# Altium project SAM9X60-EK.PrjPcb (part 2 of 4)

## Sheet 05 - Processor IO Expansions.SchDoc
size B; CompanyName: Microchip Technology Inc.; Organization: Microchip Technology; Address1: 2355 West Chandler Blvd.; Address2: Chandler, AZ  85224; Address4: USA; DocumentNumber: 5; SheetNumber: 5; SheetTotal: 13; SheetTitle: Processor IO Expansions

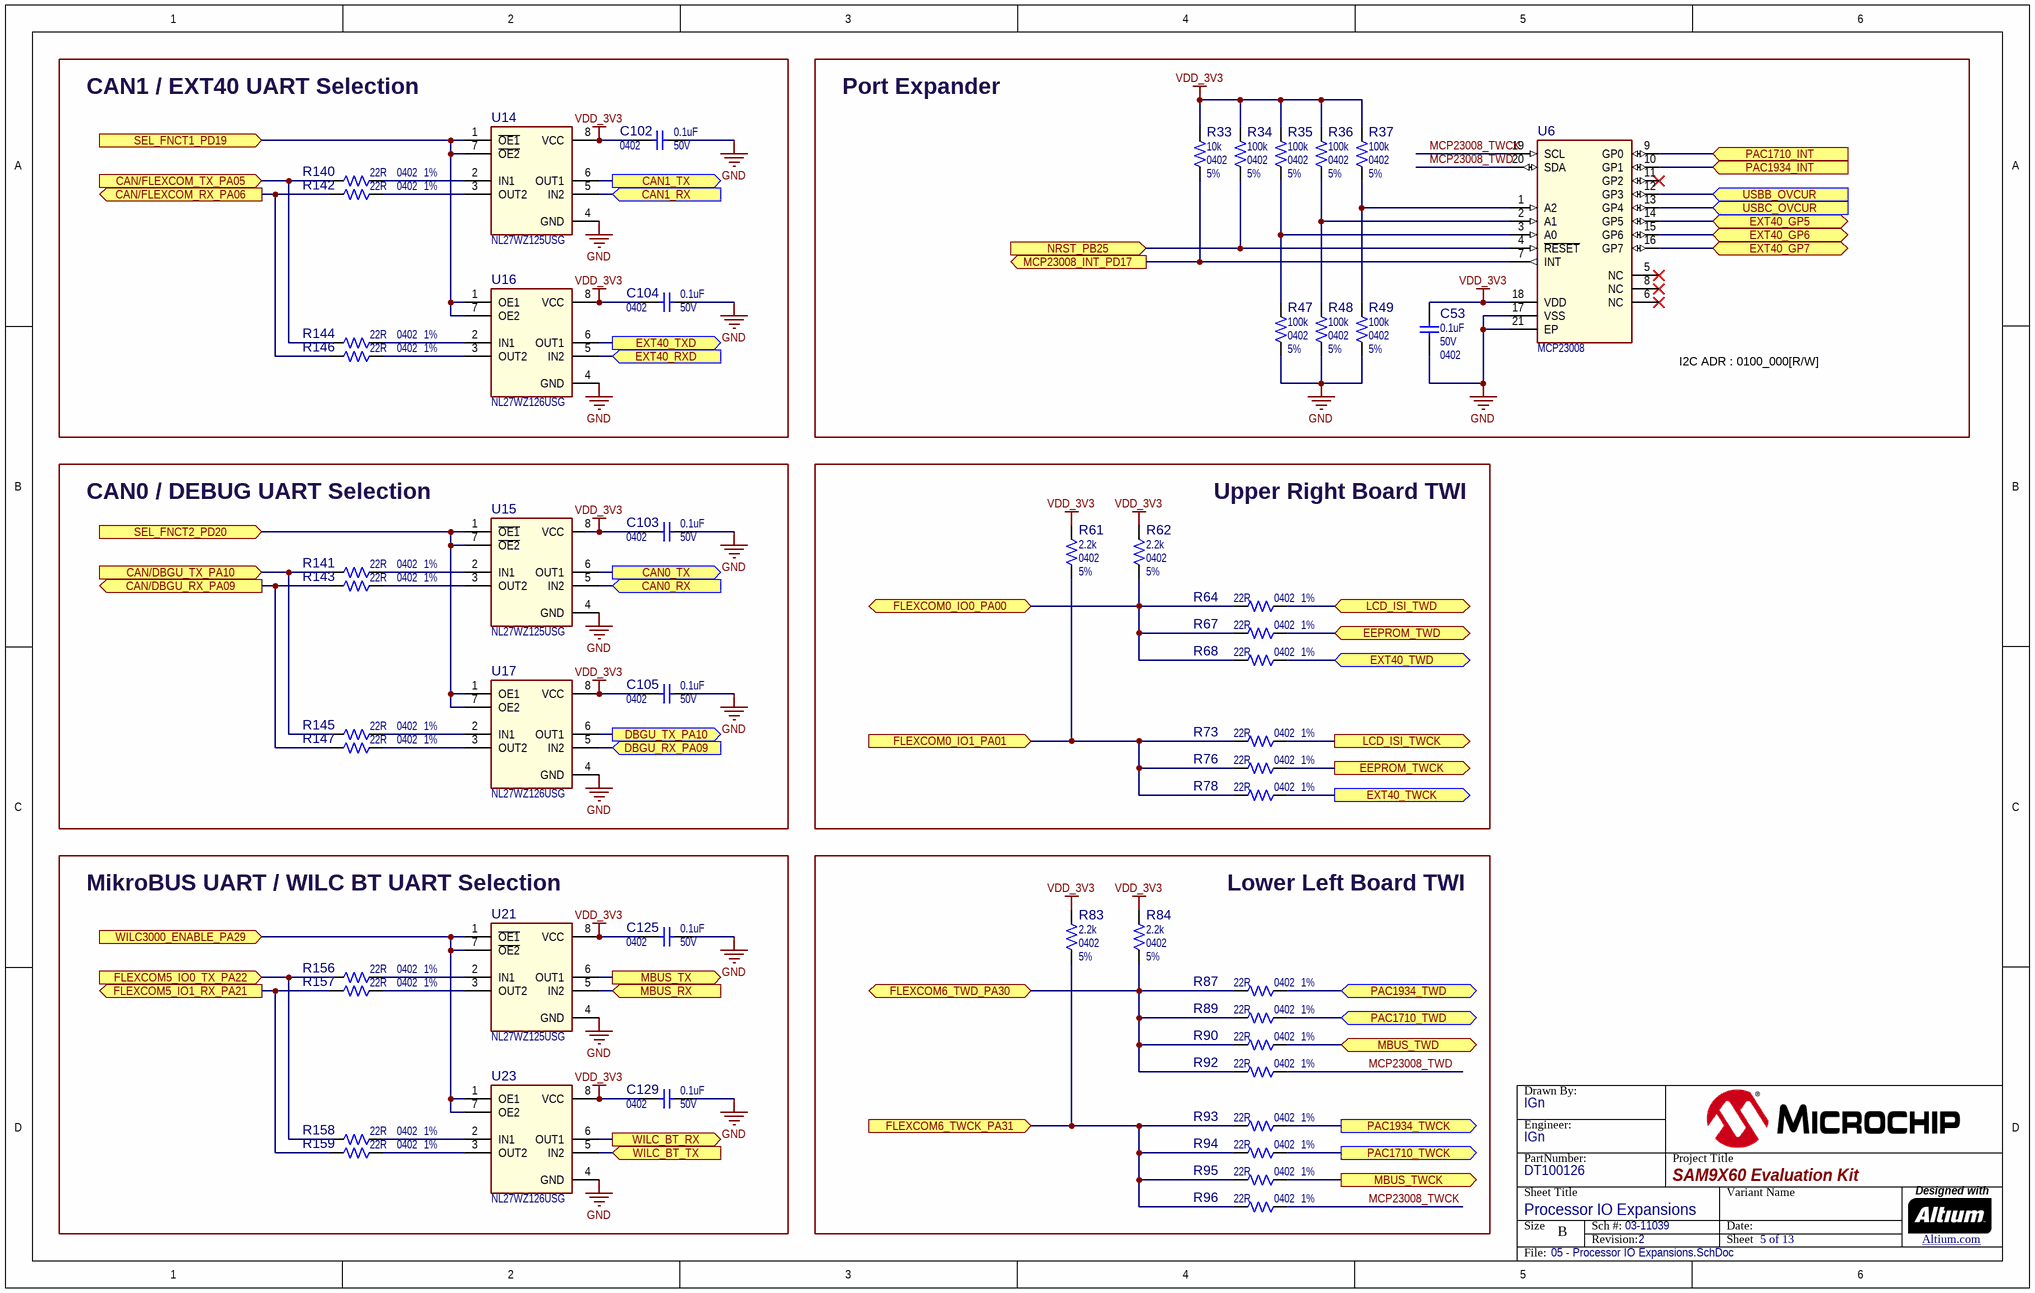
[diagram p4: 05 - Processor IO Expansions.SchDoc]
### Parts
(Parts that share a designator on the sheet are numbered #1, #2 ... from top to bottom, then left to right.)
?#5  (no value)  (graphical)
C53  value 0.1uF  Voltage: 50V  Package: 0402  [CAP_C_0402]  (hidden comment: Capacitor NP)
C102  value 0.1uF  Voltage: 50V  Package: 0402  [CAP_C_0402]  (hidden comment: Capacitor NP)
C103  value 0.1uF  Voltage: 50V  Package: 0402  [CAP_C_0402]  (hidden comment: Capacitor NP)
C104  value 0.1uF  Voltage: 50V  Package: 0402  [CAP_C_0402]  (hidden comment: Capacitor NP)
C105  value 0.1uF  Voltage: 50V  Package: 0402  [CAP_C_0402]  (hidden comment: Capacitor NP)
C125  value 0.1uF  Voltage: 50V  Package: 0402  [CAP_C_0402]  (hidden comment: Capacitor NP)
C129  value 0.1uF  Voltage: 50V  Package: 0402  [CAP_C_0402]  (hidden comment: Capacitor NP)
R33  value 10k  Package: 0402  Tolerance: 5%  [RES_C_0402]  (hidden comment: Resistor)
R34  value 100k  Package: 0402  Tolerance: 5%  [RES_C_0402]  (hidden comment: Resistor)
R35  value 100k  Package: 0402  Tolerance: 5%  [RES_C_0402]  (hidden comment: Resistor)
R36  value 100k  Package: 0402  Tolerance: 5%  [RES_C_0402]  (hidden comment: Resistor)
R37  value 100k  Package: 0402  Tolerance: 5%  [RES_C_0402]  (hidden comment: Resistor)
R47  value 100k  Package: 0402  Tolerance: 5%  [RES_C_0402]  (hidden comment: Resistor)
R48  value 100k  Package: 0402  Tolerance: 5%  [RES_C_0402]  (hidden comment: Resistor)
R49  value 100k  Package: 0402  Tolerance: 5%  [RES_C_0402]  (hidden comment: Resistor)
R61  value 2.2k  Package: 0402  Tolerance: 5%  [RES_C_0402]  (hidden comment: Resistor)
R62  value 2.2k  Package: 0402  Tolerance: 5%  [RES_C_0402]  (hidden comment: Resistor)
R64  value 22R  Package: 0402  Tolerance: 1%  [RES_C_0402]  (hidden comment: Resistor)
R67  value 22R  Package: 0402  Tolerance: 1%  [RES_C_0402]  (hidden comment: Resistor)
R68  value 22R  Package: 0402  Tolerance: 1%  [RES_C_0402]  (hidden comment: Resistor)
R73  value 22R  Package: 0402  Tolerance: 1%  [RES_C_0402]  (hidden comment: Resistor)
R76  value 22R  Package: 0402  Tolerance: 1%  [RES_C_0402]  (hidden comment: Resistor)
R78  value 22R  Package: 0402  Tolerance: 1%  [RES_C_0402]  (hidden comment: Resistor)
R83  value 2.2k  Package: 0402  Tolerance: 5%  [RES_C_0402]  (hidden comment: Resistor)
R84  value 2.2k  Package: 0402  Tolerance: 5%  [RES_C_0402]  (hidden comment: Resistor)
R87  value 22R  Package: 0402  Tolerance: 1%  [RES_C_0402]  (hidden comment: Resistor)
R89  value 22R  Package: 0402  Tolerance: 1%  [RES_C_0402]  (hidden comment: Resistor)
R90  value 22R  Package: 0402  Tolerance: 1%  [RES_C_0402]  (hidden comment: Resistor)
R92  value 22R  Package: 0402  Tolerance: 1%  [RES_C_0402]  (hidden comment: Resistor)
R93  value 22R  Package: 0402  Tolerance: 1%  [RES_C_0402]  (hidden comment: Resistor)
R94  value 22R  Package: 0402  Tolerance: 1%  [RES_C_0402]  (hidden comment: Resistor)
R95  value 22R  Package: 0402  Tolerance: 1%  [RES_C_0402]  (hidden comment: Resistor)
R96  value 22R  Package: 0402  Tolerance: 1%  [RES_C_0402]  (hidden comment: Resistor)
R140  value 22R  Package: 0402  Tolerance: 1%  [RES_C_0402]  (hidden comment: Resistor)
R141  value 22R  Package: 0402  Tolerance: 1%  [RES_C_0402]  (hidden comment: Resistor)
R142  value 22R  Package: 0402  Tolerance: 1%  [RES_C_0402]  (hidden comment: Resistor)
R143  value 22R  Package: 0402  Tolerance: 1%  [RES_C_0402]  (hidden comment: Resistor)
R144  value 22R  Package: 0402  Tolerance: 1%  [RES_C_0402]  (hidden comment: Resistor)
R145  value 22R  Package: 0402  Tolerance: 1%  [RES_C_0402]  (hidden comment: Resistor)
R146  value 22R  Package: 0402  Tolerance: 1%  [RES_C_0402]  (hidden comment: Resistor)
R147  value 22R  Package: 0402  Tolerance: 1%  [RES_C_0402]  (hidden comment: Resistor)
R156  value 22R  Package: 0402  Tolerance: 1%  [RES_C_0402]  (hidden comment: Resistor)
R157  value 22R  Package: 0402  Tolerance: 1%  [RES_C_0402]  (hidden comment: Resistor)
R158  value 22R  Package: 0402  Tolerance: 1%  [RES_C_0402]  (hidden comment: Resistor)
R159  value 22R  Package: 0402  Tolerance: 1%  [RES_C_0402]  (hidden comment: Resistor)
U6  value MCP23008  [QFN-20_4x4]  (hidden comment: MCP23008 QFN-20)
U14  value NL27WZ125USG  [US-8]  (hidden comment: NL27WZ125 US-8)
U15  value NL27WZ125USG  [US-8]  (hidden comment: NL27WZ125 US-8)
U16  value NL27WZ126USG  [US-8]  (hidden comment: NL27WZ126 US-8)
U17  value NL27WZ126USG  [US-8]  (hidden comment: NL27WZ126 US-8)
U21  value NL27WZ125USG  [US-8]  (hidden comment: NL27WZ125 US-8)
U23  value NL27WZ126USG  [US-8]  (hidden comment: NL27WZ126 US-8)

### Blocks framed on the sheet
CAN1 / EXT40 UART Selection: C102 C104 R140 R142 R144 R146 U14 U16
Port Expander: C53 R33-R37 R47-R49 U6
CAN0 / DEBUG UART Selection: C103 C105 R141 R143 R145 R147 U15 U17
Upper Right Board TWI: R61 R62 R64 R67 R68 R73 R76 R78
MikroBUS UART / WILC BT UART Selection: C125 C129 R156-R159 U21 U23
Lower Left Board TWI: R83 R84 R87 R89 R90 R92-R96

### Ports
CAN0_RX (in), CAN0_TX (out), CAN1_RX (in), CAN1_TX (out), CAN/DBGU_RX_PA09 (out), CAN/DBGU_TX_PA10 (in), CAN/FLEXCOM_RX_PA06 (out), CAN/FLEXCOM_TX_PA05 (in), DBGU_RX_PA09 (in), DBGU_TX_PA10 (out), EEPROM_TWCK (out), EEPROM_TWD (bidir), EXT40_GP5 (bidir), EXT40_GP6 (bidir), EXT40_GP7 (bidir), EXT40_RXD (in), EXT40_TWCK (out), EXT40_TWD (bidir), EXT40_TXD (out), FLEXCOM0_IO0_PA00 (bidir), FLEXCOM0_IO1_PA01 (in), FLEXCOM5_IO0_TX_PA22 (in), FLEXCOM5_IO1_RX_PA21 (out), FLEXCOM6_TWCK_PA31 (in), FLEXCOM6_TWD_PA30 (bidir), LCD_ISI_TWCK (out), LCD_ISI_TWD (bidir), MBUS_RX (in), MBUS_TWCK (out), MBUS_TWD (bidir), MBUS_TX (out), MCP23008_INT_PD17 (out), NRST_PB25 (in), PAC1710_INT (in), PAC1710_TWCK (out), PAC1710_TWD (bidir), PAC1934_INT (in), PAC1934_TWCK (out), PAC1934_TWD (bidir), SEL_FNCT1_PD19 (in), SEL_FNCT2_PD20 (in), USBB_OVCUR (in), USBC_OVCUR (in), WILC3000_ENABLE_PA29 (in), WILC_BT_RX (out), WILC_BT_TX (in)

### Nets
GND: C53.2 C102.2 C103.2 C104.2 C105.2 C125.2 C129.2 R47.1 R48.1 R49.1 U6.17(VSS) U6.21(EP) U14.4(GND) U15.4(GND) U16.4(GND) U17.4(GND) U21.4(GND) U23.4(GND)
VDD_3V3: C53.1 C102.1 C103.1 C104.1 C105.1 C125.1 C129.1 R33.2 R34.2 R35.2 R36.2 R37.2 R61.2 R62.2 R83.2 R84.2 U6.18(VDD) U14.8(VCC) U15.8(VCC) U16.8(VCC) U17.8(VCC) U21.8(VCC) U23.8(VCC)
CAN0_RX: U15.5(IN2) ; port CAN0_RX
CAN0_TX: U15.6(OUT1) ; port CAN0_TX
CAN1_RX: U14.5(IN2) ; port CAN1_RX
CAN1_TX: U14.6(OUT1) ; port CAN1_TX
CAN/DBGU_RX_PA09: R143.2 R147.2 ; port CAN/DBGU_RX_PA09
CAN/DBGU_TX_PA10: R141.2 R145.2 ; port CAN/DBGU_TX_PA10
CAN/FLEXCOM_RX_PA06: R142.2 R146.2 ; port CAN/FLEXCOM_RX_PA06
CAN/FLEXCOM_TX_PA05: R140.2 R144.2 ; port CAN/FLEXCOM_TX_PA05
DBGU_RX_PA09: U17.5(IN2) ; port DBGU_RX_PA09
DBGU_TX_PA10: U17.6(OUT1) ; port DBGU_TX_PA10
EEPROM_TWCK: R76.2 ; port EEPROM_TWCK
EEPROM_TWD: R67.2 ; port EEPROM_TWD
EXT40_GP5: U6.14(GP5) ; port EXT40_GP5
EXT40_GP6: U6.15(GP6) ; port EXT40_GP6
EXT40_GP7: U6.16(GP7) ; port EXT40_GP7
EXT40_RXD: U16.5(IN2) ; port EXT40_RXD
EXT40_TWCK: R78.2 ; port EXT40_TWCK
EXT40_TWD: R68.2 ; port EXT40_TWD
EXT40_TXD: U16.6(OUT1) ; port EXT40_TXD
FLEXCOM0_IO0_PA00: R62.1 R64.1 R67.1 R68.1 ; port FLEXCOM0_IO0_PA00
FLEXCOM0_IO1_PA01: R61.1 R73.1 R76.1 R78.1 ; port FLEXCOM0_IO1_PA01
FLEXCOM5_IO0_TX_PA22: R156.2 R158.2 ; port FLEXCOM5_IO0_TX_PA22
FLEXCOM5_IO1_RX_PA21: R157.2 R159.2 ; port FLEXCOM5_IO1_RX_PA21
FLEXCOM6_TWCK_PA31: R83.1 R93.1 R94.1 R95.1 R96.1 ; port FLEXCOM6_TWCK_PA31
FLEXCOM6_TWD_PA30: R84.1 R87.1 R89.1 R90.1 R92.1 ; port FLEXCOM6_TWD_PA30
LCD_ISI_TWCK: R73.2 ; port LCD_ISI_TWCK
LCD_ISI_TWD: R64.2 ; port LCD_ISI_TWD
MBUS_RX: U21.5(IN2) ; port MBUS_RX
MBUS_TWCK: R95.2 ; port MBUS_TWCK
MBUS_TWD: R90.2 ; port MBUS_TWD
MBUS_TX: U21.6(OUT1) ; port MBUS_TX
MCP23008_INT_PD17: R33.1 U6.7(INT) ; port MCP23008_INT_PD17
MCP23008_TWCK: R96.2 U6.19(SCL)
MCP23008_TWD: R92.2 U6.20(SDA)
NRST_PB25: R34.1 U6.4(~{RESET}) ; port NRST_PB25
PAC1710_INT: U6.9(GP0) ; port PAC1710_INT
PAC1710_TWCK: R94.2 ; port PAC1710_TWCK
PAC1710_TWD: R89.2 ; port PAC1710_TWD
PAC1934_INT: U6.10(GP1) ; port PAC1934_INT
PAC1934_TWCK: R93.2 ; port PAC1934_TWCK
PAC1934_TWD: R87.2 ; port PAC1934_TWD
SEL_FNCT1_PD19: U14.1(~{OE1}) U14.7(~{OE2}) U16.1(OE1) U16.7(OE2) ; port SEL_FNCT1_PD19
SEL_FNCT2_PD20: U15.1(~{OE1}) U15.7(~{OE2}) U17.1(OE1) U17.7(OE2) ; port SEL_FNCT2_PD20
USBB_OVCUR: U6.12(GP3) ; port USBB_OVCUR
USBC_OVCUR: U6.13(GP4) ; port USBC_OVCUR
WILC3000_ENABLE_PA29: U21.1(~{OE1}) U21.7(~{OE2}) U23.1(OE1) U23.7(OE2) ; port WILC3000_ENABLE_PA29
WILC_BT_RX: U23.6(OUT1) ; port WILC_BT_RX
WILC_BT_TX: U23.5(IN2) ; port WILC_BT_TX
NetR35_1: R35.1 R47.2 U6.3(A0)
NetR36_1: R36.1 R48.2 U6.2(A1)
NetR37_1: R37.1 R49.2 U6.1(A2)
NetR140_1: R140.1 U14.2(IN1)
NetR141_1: R141.1 U15.2(IN1)
NetR142_1: R142.1 U14.3(OUT2)
NetR143_1: R143.1 U15.3(OUT2)
NetR144_1: R144.1 U16.2(IN1)
NetR145_1: R145.1 U17.2(IN1)
NetR146_1: R146.1 U16.3(OUT2)
NetR147_1: R147.1 U17.3(OUT2)
NetR156_1: R156.1 U21.2(IN1)
NetR157_1: R157.1 U21.3(OUT2)
NetR158_1: R158.1 U23.2(IN1)
NetR159_1: R159.1 U23.3(OUT2)

Not connected (* = marked no-connect by the designer): U6 5(NC)* 6(NC)* 8(NC)* 11(GP2)*

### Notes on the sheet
- (near U6) I2C ADR : 0100_000[R/W]

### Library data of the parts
?#5 = Title Block B
C53 C102-C105 C125 C129 = CAP1463: Capacitor; Manufacturer 1: TDK Corporation; Manufacturer Part Number 1: C1005X7R1H104K050BB; Description_: CAP CER 0.1uF 50V 10% X7R SMD 0402; Dev Tools Status: Production; Tolerance: 10%; Temperature Coeffcient: X7R; Type: Ceramic; Owner: Jamus Griego; Populated: YES
R33 = RSMT0439: Manufacturer 1: Vishay; Manufacturer Part Number 1: CRCW040210K0JNED; Description_: RES TKF 10k 5% 1/16W SMD 0402; Dev Tools Status: Production; Voltage: 50V; Temperature Coeffcient: 100ppm/C; Power: 1/16W; Populated: Yes
R34 R47-R49 = RES2196: Manufacturer 1: Yageo; Manufacturer Part Number 1: RC0402JR-07100KL; Description_: RES TKF 100k 5% 1/16W SMD 0402; Dev Tools Status: Design; Temperature Coeffcient: 100ppm/C; Power: 1/16W; Owner: Ilie Galan; Populated: YES
R35-R37 = RES2196: Manufacturer 1: Yageo; Manufacturer Part Number 1: RC0402JR-07100KL; Description_: RES TKF 100k 5% 1/16W SMD 0402; Dev Tools Status: Design; Temperature Coeffcient: 100ppm/C; Power: 1/16W; Owner: Ilie Galan; Populated: DNP
R61 R62 R83 R84 = RES1020: Manufacturer 1: Vishay Dale; Manufacturer Part Number 1: CRCW04022K20JNED; Description_: RES TKF 2.2k 5% 1/16W SMD 0402; Dev Tools Status: Production; Voltage: 50V; Temperature Coeffcient: 200ppm/C; Power: 1/16W; Owner: Tad Ahlvers; Populated: YES
R64 R67 R68 R73 R76 R78 R87 R89 R90 R92-R96 R140-R147 R156-R159 = RES1474: Manufacturer 1: Panasonic Electronic Components; Manufacturer Part Number 1: ERJ-2RKF22R0X; Description_: RES TKF 22R 1% 1/20W SMD 0402; Dev Tools Status: Production; Temperature Coeffcient: 100ppm/C; Circuit Type: Isolated; Power: 1/10W; Owner: Mike Ragsdale; Populated: YES
U6 = MIC2806: I/O Expander; Manufacturer 1: Microchip; Manufacturer Part Number 1: MCP23008T-E/ML; Description_: MCHP INTERFACE GPIO-PORT EXPAND I2C 8-Port MCP23008-E/ML QFN-20; MAPS Description: 8 BIT INPUT/OUTPUT EXPANDER, I2C INTERFACE; Dev Tools Status: Production; MPC: C5BQ1YG4XA00; LeadContent: Pb-FREE; PackingMedia: T/R; Stage: REL; LeadCount: 20; PackageWidth: 4x4x0.9mm; ForceMinOrderQtyMult: True; MinOrderQty: 1; TempRange: -40C to +125C; tblDeviceFamilyID: 1180; OperatingVoltageMin: 1.8; OperatingVoltageMax: 5.5; IOpins: 8; Interface: 524288; Speed: 1.7M; HWAddressPins: 3; ResetPin: Yes; PinCurrent: 25; TotalCurrent: 160; IOVoltageTolerant: VDD
U14 U15 U21 = IC1512: BUFFER DL TRI-ST NON-INV; Manufacturer 1: ON Semiconductor; MCHP-ID: IC1512; Description_: IC BUFFER NL27WZ125USG DUAL TRI-ST NON-INV US-8; Dev Tools Status: Design; Vin: 5V; Owner: Ciprian Abramov; Populated: YES
U16 U17 U23 = IC1514: BUFFER DL TRI-ST NON-INV; Manufacturer 1: ON Semiconductor; MCHP-ID: IC1514; Description_: IC BUFFER NL27WZ126USG DUAL TRI-ST NON-INV US-8; Dev Tools Status: Design; Vin: 5V; Owner: Ciprian Abramov; Populated: YES

## Sheet 06 - On Board Memories.SchDoc
size B; CompanyName: Microchip Technology Inc.; Organization: Microchip Technology; Address1: 2355 West Chandler Blvd.; Address2: Chandler, AZ  85224; Address4: USA; DocumentNumber: 6; SheetNumber: 6; SheetTotal: 13; SheetTitle: On Board Memories

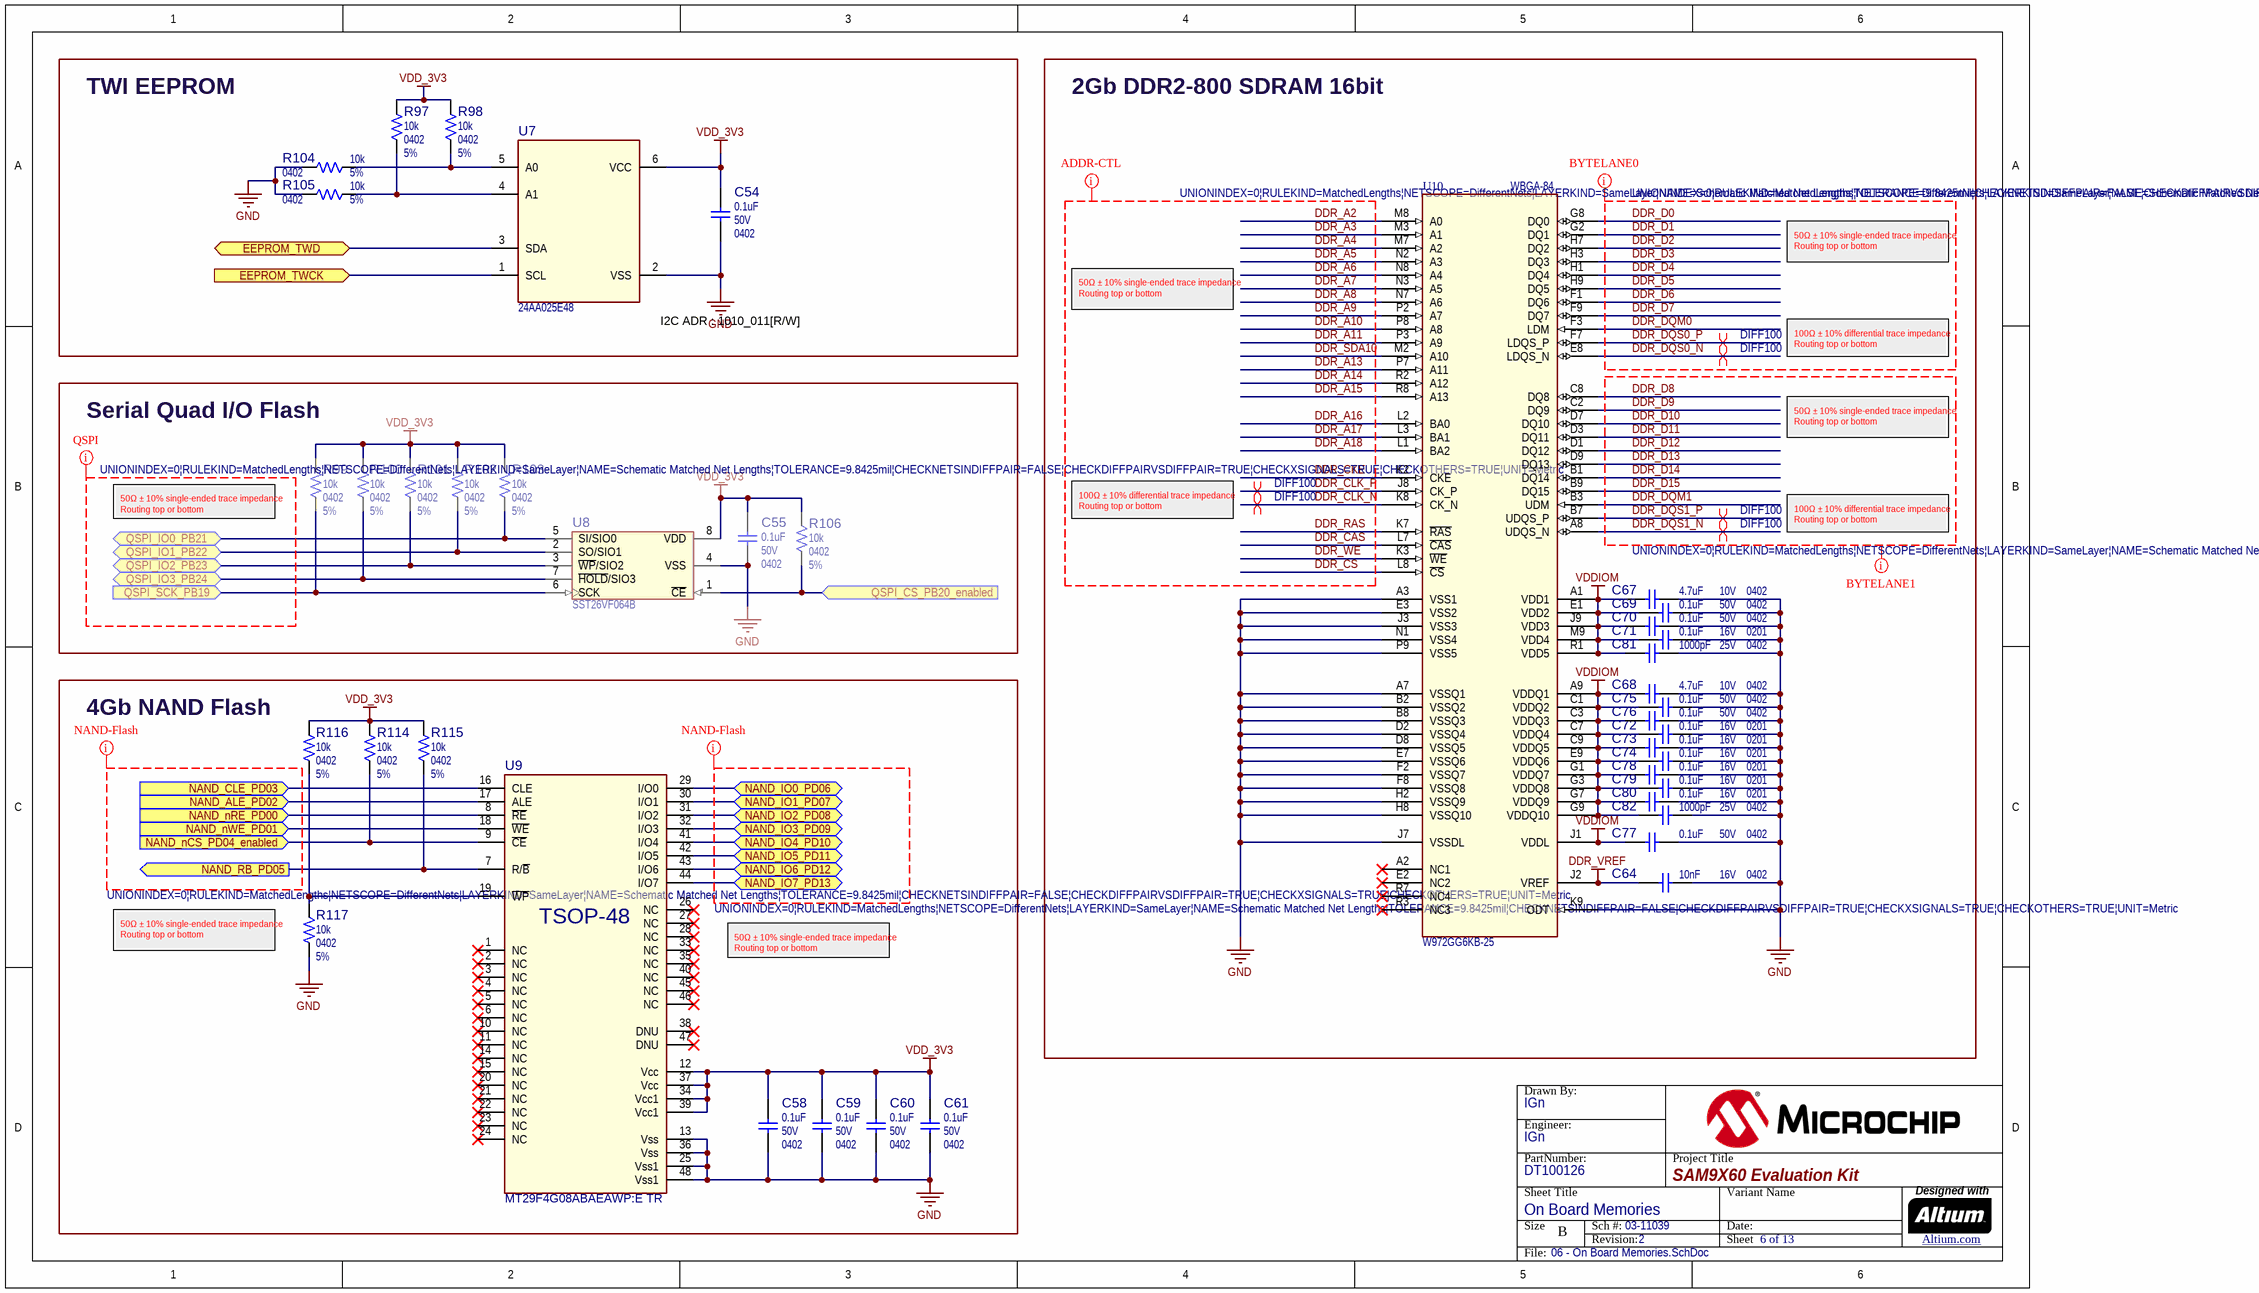
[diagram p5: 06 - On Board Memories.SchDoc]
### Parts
(Parts that share a designator on the sheet are numbered #1, #2 ... from top to bottom, then left to right.)
?#6  (no value)  (graphical)
C54  value 0.1uF  Voltage: 50V  Package: 0402  [CAP_C_0402]  (hidden comment: Capacitor NP)
C55  value 0.1uF  Voltage: 50V  Package: 0402  [CAP_C_0402]  (hidden comment: Capacitor NP)
C58  value 0.1uF  Voltage: 50V  Package: 0402  [CAP_C_0402]  (hidden comment: Capacitor NP)
C59  value 0.1uF  Voltage: 50V  Package: 0402  [CAP_C_0402]  (hidden comment: Capacitor NP)
C60  value 0.1uF  Voltage: 50V  Package: 0402  [CAP_C_0402]  (hidden comment: Capacitor NP)
C61  value 0.1uF  Voltage: 50V  Package: 0402  [CAP_C_0402]  (hidden comment: Capacitor NP)
C64  value 10nF  Voltage: 16V  Package: 0402  [CAP_C_0402]  (hidden comment: Capacitor NP)
C67  value 4.7uF  Voltage: 10V  Package: 0402  [CAP_C_0402]  (hidden comment: Capacitor NP)
C68  value 4.7uF  Voltage: 10V  Package: 0402  [CAP_C_0402]  (hidden comment: Capacitor NP)
C69  value 0.1uF  Voltage: 50V  Package: 0402  [CAP_C_0402]  (hidden comment: Capacitor NP)
C70  value 0.1uF  Voltage: 50V  Package: 0402  [CAP_C_0402]  (hidden comment: Capacitor NP)
C71  value 0.1uF  Voltage: 16V  Package: 0201  [CAP_C_0201]  (hidden comment: Capacitor NP)
C72  value 0.1uF  Voltage: 16V  Package: 0201  [CAP_C_0201]  (hidden comment: Capacitor NP)
C73  value 0.1uF  Voltage: 16V  Package: 0201  [CAP_C_0201]  (hidden comment: Capacitor NP)
C74  value 0.1uF  Voltage: 16V  Package: 0201  [CAP_C_0201]  (hidden comment: Capacitor NP)
C75  value 0.1uF  Voltage: 50V  Package: 0402  [CAP_C_0402]  (hidden comment: Capacitor NP)
C76  value 0.1uF  Voltage: 50V  Package: 0402  [CAP_C_0402]  (hidden comment: Capacitor NP)
C77  value 0.1uF  Voltage: 50V  Package: 0402  [CAP_C_0402]  (hidden comment: Capacitor NP)
C78  value 0.1uF  Voltage: 16V  Package: 0201  [CAP_C_0201]  (hidden comment: Capacitor NP)
C79  value 0.1uF  Voltage: 16V  Package: 0201  [CAP_C_0201]  (hidden comment: Capacitor NP)
C80  value 0.1uF  Voltage: 16V  Package: 0201  [CAP_C_0201]  (hidden comment: Capacitor NP)
C81  value 1000pF  Voltage: 25V  Package: 0402  [CAP_C_0402]  (hidden comment: Capacitor NP)
C82  value 1000pF  Voltage: 25V  Package: 0402  [CAP_C_0402]  (hidden comment: Capacitor NP)
R97  value 10k  Package: 0402  Tolerance: 5%  [RES_C_0402]  (hidden comment: Resistor)
R98  value 10k  Package: 0402  Tolerance: 5%  [RES_C_0402]  (hidden comment: Resistor)
R99  value 10k  Package: 0402  Tolerance: 5%  [RES_C_0402]  (hidden comment: Resistor)
R100  value 10k  Package: 0402  Tolerance: 5%  [RES_C_0402]  (hidden comment: Resistor)
R101  value 10k  Package: 0402  Tolerance: 5%  [RES_C_0402]  (hidden comment: Resistor)
R102  value 10k  Package: 0402  Tolerance: 5%  [RES_C_0402]  (hidden comment: Resistor)
R103  value 10k  Package: 0402  Tolerance: 5%  [RES_C_0402]  (hidden comment: Resistor)
R104  value 10k  Package: 0402  Tolerance: 5%  [RES_C_0402]  (hidden comment: Resistor)
R105  value 10k  Package: 0402  Tolerance: 5%  [RES_C_0402]  (hidden comment: Resistor)
R106  value 10k  Package: 0402  Tolerance: 5%  [RES_C_0402]  (hidden comment: Resistor)
R114  value 10k  Package: 0402  Tolerance: 5%  [RES_C_0402]  (hidden comment: Resistor)
R115  value 10k  Package: 0402  Tolerance: 5%  [RES_C_0402]  (hidden comment: Resistor)
R116  value 10k  Package: 0402  Tolerance: 5%  [RES_C_0402]  (hidden comment: Resistor)
R117  value 10k  Package: 0402  Tolerance: 5%  [RES_C_0402]  (hidden comment: Resistor)
U7  value 24AA025E48  [SOT-23-6]  (hidden comment: 24XXXX SOT-23-6)
U8  value SST26VF064B  [SOIJ-8]  (hidden comment: SST26VFXXX SOIC-8_WSON-8_SOIJ-8)
U9  value MT29F4G08ABAEAWP:E TR  Package: TSOP-48  [TSOP-48_P0.5]  (hidden comment: MT29F4G08ABA TSOP-48)
U10  value W972GG6KB-25  Package: WBGA-84  [WBGA-84_P0.8_8x12.5x1.2]  (hidden comment: W972GG6KB-25 WBGA-84)

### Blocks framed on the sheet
TWI EEPROM: C54 R97 R98 R104 R105 U7
2Gb DDR2-800 SDRAM 16bit: C64 C67-C82 U10
Serial Quad I/O Flash: C55 R99-R103 R106 U8
4Gb NAND Flash: C58-C61 R114-R117 U9

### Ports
EEPROM_TWCK (in), EEPROM_TWD (bidir), NAND_ALE_PD02 (in), NAND_CLE_PD03 (in), NAND_IO0_PD06 (bidir), NAND_IO1_PD07 (bidir), NAND_IO2_PD08 (bidir), NAND_IO3_PD09 (bidir), NAND_IO4_PD10 (bidir), NAND_IO5_PD11 (bidir), NAND_IO6_PD12 (bidir), NAND_IO7_PD13 (bidir), NAND_nCS_PD04_enabled (in), NAND_nRE_PD00 (in), NAND_nWE_PD01 (in), NAND_RB_PD05 (out), QSPI_CS_PB20_enabled (in), QSPI_IO0_PB21 (bidir), QSPI_IO1_PB22 (bidir), QSPI_IO2_PB23 (bidir), QSPI_IO3_PB24 (bidir), QSPI_SCK_PB19 (in)

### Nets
DDR_VREF: C64.1 U10.J2(VREF)
GND: C54.2 C55.2 C58.2 C59.2 C60.2 C61.2 C64.2 C67.1 C68.1 C69.2 C70.2 C71.1 C72.1 C73.1 C74.1 C75.2 C76.2 C77.2 C78.1 C79.1 C80.1 C81.1 C82.1 R104.2 R105.2 R117.1 U7.2(VSS) U8.4(VSS) U9.13(Vss) U9.25(Vss1) U9.36(Vss) U9.48(Vss1) U10.A3(VSS1) U10.A7(VSSQ1) U10.B2(VSSQ2) U10.B8(VSSQ3) U10.D2(VSSQ4) U10.D8(VSSQ5) U10.E3(VSS2) U10.E7(VSSQ6) U10.F2(VSSQ7) U10.F8(VSSQ8) U10.H2(VSSQ9) U10.H8(VSSQ10) U10.J3(VSS3) U10.J7(VSSDL) U10.K9(ODT) U10.N1(VSS4) U10.P9(VSS5)
VDD_3V3: C54.1 C55.1 C58.1 C59.1 C60.1 C61.1 R97.2 R98.2 R99.2 R100.2 R101.2 R102.2 R103.2 R106.2 R114.2 R115.2 R116.2 U7.6(VCC) U8.8(VDD) U9.12(Vcc) U9.34(Vcc1) U9.37(Vcc) U9.39(Vcc1)
VDDIOM: C67.2 C68.2 C69.1 C70.1 C71.2 C72.2 C73.2 C74.2 C75.1 C76.1 C77.1 C78.2 C79.2 C80.2 C81.2 C82.2 U10.A1(VDD1) U10.A9(VDDQ1) U10.C1(VDDQ2) U10.C3(VDDQ3) U10.C7(VDDQ4) U10.C9(VDDQ5) U10.E1(VDD2) U10.E9(VDDQ6) U10.G1(VDDQ7) U10.G3(VDDQ8) U10.G7(VDDQ9) U10.G9(VDDQ10) U10.J1(VDDL) U10.J9(VDD3) U10.M9(VDD4) U10.R1(VDD5)
DDR_A2: U10.M8(A0)
DDR_A3: U10.M3(A1)
DDR_A4: U10.M7(A2)
DDR_A5: U10.N2(A3)
DDR_A6: U10.N8(A4)
DDR_A7: U10.N3(A5)
DDR_A8: U10.N7(A6)
DDR_A9: U10.P2(A7)
DDR_A10: U10.P8(A8)
DDR_A11: U10.P3(A9)
DDR_A13: U10.P7(A11)
DDR_A14: U10.R2(A12)
DDR_A15: U10.R8(A13)
DDR_A16: U10.L2(BA0)
DDR_A17: U10.L3(BA1)
DDR_A18: U10.L1(BA2)
DDR_CAS: U10.L7(~{CAS})
DDR_CKE: U10.K2(CKE)
DDR_CLK_N: U10.K8(CK_N)
DDR_CLK_P: U10.J8(CK_P)
DDR_CS: U10.L8(~{CS})
DDR_D0: U10.G8(DQ0)
DDR_D1: U10.G2(DQ1)
DDR_D2: U10.H7(DQ2)
DDR_D3: U10.H3(DQ3)
DDR_D4: U10.H1(DQ4)
DDR_D5: U10.H9(DQ5)
DDR_D6: U10.F1(DQ6)
DDR_D7: U10.F9(DQ7)
DDR_D8: U10.C8(DQ8)
DDR_D9: U10.C2(DQ9)
DDR_D10: U10.D7(DQ10)
DDR_D11: U10.D3(DQ11)
DDR_D12: U10.D1(DQ12)
DDR_D13: U10.D9(DQ13)
DDR_D14: U10.B1(DQ14)
DDR_D15: U10.B9(DQ15)
DDR_DQM0: U10.F3(LDM)
DDR_DQM1: U10.B3(UDM)
DDR_DQS0_N: U10.E8(LDQS_N)
DDR_DQS0_P: U10.F7(LDQS_P)
DDR_DQS1_N: U10.A8(UDQS_N)
DDR_DQS1_P: U10.B7(UDQS_P)
DDR_RAS: U10.K7(~{RAS})
DDR_SDA10: U10.M2(A10)
DDR_WE: U10.K3(~{WE})
EEPROM_TWCK: U7.1(SCL) ; port EEPROM_TWCK
EEPROM_TWD: U7.3(SDA) ; port EEPROM_TWD
NAND_ALE_PD02: U9.17(ALE) ; port NAND_ALE_PD02
NAND_CLE_PD03: U9.16(CLE) ; port NAND_CLE_PD03
NAND_IO0_PD06: U9.29(I/O0) ; port NAND_IO0_PD06
NAND_IO1_PD07: U9.30(I/O1) ; port NAND_IO1_PD07
NAND_IO2_PD08: U9.31(I/O2) ; port NAND_IO2_PD08
NAND_IO3_PD09: U9.32(I/O3) ; port NAND_IO3_PD09
NAND_IO4_PD10: U9.41(I/O4) ; port NAND_IO4_PD10
NAND_IO5_PD11: U9.42(I/O5) ; port NAND_IO5_PD11
NAND_IO6_PD12: U9.43(I/O6) ; port NAND_IO6_PD12
NAND_IO7_PD13: U9.44(I/O7) ; port NAND_IO7_PD13
NAND_nCS_PD04_enabled: R114.1 U9.9(~{CE}) ; port NAND_nCS_PD04_enabled
NAND_nRE_PD00: U9.8(~{RE}) ; port NAND_nRE_PD00
NAND_nWE_PD01: U9.18(~{WE}) ; port NAND_nWE_PD01
NAND_RB_PD05: R115.1 U9.7(R/~{B}) ; port NAND_RB_PD05
QSPI_CS_PB20_enabled: R106.1 U8.1(~{CE}) ; port QSPI_CS_PB20_enabled
QSPI_IO0_PB21: R103.1 U8.5(SI/SIO0) ; port QSPI_IO0_PB21
QSPI_IO1_PB22: R102.1 U8.2(SO/SIO1) ; port QSPI_IO1_PB22
QSPI_IO2_PB23: R101.1 U8.3(~{WP}/SIO2) ; port QSPI_IO2_PB23
QSPI_IO3_PB24: R100.1 U8.7(~{HOLD}/SIO3) ; port QSPI_IO3_PB24
QSPI_SCK_PB19: R99.1 U8.6(SCK) ; port QSPI_SCK_PB19
NetR97_1: R97.1 R105.1 U7.4(A1)
NetR98_1: R98.1 R104.1 U7.5(A0)
NetR116_1: R116.1 R117.2 U9.19(~{WP})

Not connected (* = marked no-connect by the designer): U9 1(NC)* 2(NC)* 3(NC)* 4(NC)* 5(NC)* 6(NC)* 10(NC)* 11(NC)* 14(NC)* 15(NC)* 20(NC)* 21(NC)* 22(NC)* 23(NC)* 24(NC)* 26(NC)* 27(NC)* 28(NC)* 33(NC)* 35(NC)* 38(DNU)* 40(NC)* 45(NC)* 46(NC)* 47(DNU)*; U10 A2(NC1)* E2(NC2)* R3(NC3)* R7(NC4)*

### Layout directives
net class NAND-Flash; rule Matched Net Lengths [Tolerance = 0.25mm]: (no net found under the mark)
net class DDR-LANE0; rule Matched Net Lengths [Tolerance = 0.25mm]: DDR_D0, DDR_D1, DDR_D2, DDR_D3, DDR_D4, DDR_D5, DDR_D6, DDR_D7, DDR_DQM0, DDR_DQS0_N, DDR_DQS0_P
net class DDR-ADD-CTL; rule Matched Net Lengths [Tolerance = 0.25mm]: DDR_A2, DDR_A3, DDR_A4, DDR_A5, DDR_A6, DDR_A7, DDR_A8, DDR_A9, DDR_A10, DDR_A11, DDR_A13, DDR_A14, DDR_A15, DDR_A16, DDR_A17, DDR_A18, DDR_CAS, DDR_CKE, DDR_CLK_N, DDR_CLK_P, DDR_CS, DDR_RAS, DDR_SDA10, DDR_WE
net class DDR-LANE1; rule Matched Net Lengths [Tolerance = 0.25mm]: DDR_D8, DDR_D9, DDR_D10, DDR_D11, DDR_D12, DDR_D13, DDR_D14, DDR_D15, DDR_DQM1, DDR_DQS1_N, DDR_DQS1_P
differential pair; differential pair class DIFF100; net class DIFF100; rule Matched Net Lengths [Tolerance = 10mil]: DDR_CLK_N, DDR_CLK_P, DDR_DQS0_N, DDR_DQS0_P, DDR_DQS1_N, DDR_DQS1_P
net class Q-SPI; rule Matched Net Lengths [Tolerance = 0.25mm]: (no net found under the mark)

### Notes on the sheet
- 50Ω ± 10% single-ended trace impedance
  Routing top or bottom
- (near U7) I2C ADR : 1010_011[R/W]
- 100Ω ± 10% differential trace impedance
  Routing top or bottom
- (near R99) 50Ω ± 10% single-ended trace impedance
  Routing top or bottom
- (near R117) 50Ω ± 10% single-ended trace impedance
  Routing top or bottom

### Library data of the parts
?#6 = Title Block B
C54 C55 C58-C61 = CAP1463: Capacitor; Manufacturer 1: TDK Corporation; Manufacturer Part Number 1: C1005X7R1H104K050BB; Description_: CAP CER 0.1uF 50V 10% X7R SMD 0402; Dev Tools Status: Production; Tolerance: 10%; Temperature Coeffcient: X7R; Type: Ceramic; Populated: YES; Owner: Jamus Griego
C64 = CAP0278: Capacitor; Manufacturer 1: KEMET; Manufacturer Part Number 1: C0402C103K4RACTU; Description_: CAP CER 10000pF 16V 10% X7R SMD 0402; Dev Tools Status: Production; Tolerance: 10%; Temperature Coeffcient: X7R; Type: Ceramic; Populated: YES
C67 C68 = CAP1684: Capacitor; Manufacturer 1: TDK Corporation; Manufacturer Part Number 1: C1005X5R1A475K050BC; Description_: CAP CER 4.7uF 10V 10% X5R SMD 0402; Dev Tools Status: Production; Tolerance: 10%; Temperature Coeffcient: X5R; Type: Ceramic; Owner: Jesus Aviles; Populated: YES
C69 C70 C75-C77 = CAP1463: as C53 on sheet 05 - Processor IO Expansions
C71-C74 C78-C80 = CAP1203: Capacitor; Manufacturer 1: Murata; Manufacturer Part Number 1: GRM033R61C104KE84D; Description_: CAP CER 0.1uF 16V 10% X5R SMD 0201; Dev Tools Status: Production; Tolerance: 10%; Temperature Coeffcient: X5R; Type: Ceramic; Owner: Tad Ahlvers; Populated: YES
C81 C82 = CAP0566: Capacitor; Manufacturer 1: TDK; Manufacturer Part Number 1: C1005C0G1E102J; Description_: CAP CER 1000pF 25V 5% C0G SMD 0402; Dev Tools Status: Production; Tolerance: 5%; Temperature Coeffcient: C0G; Type: Ceramic; Populated: Yes
R97 R98 R106 R114-R116 = RSMT0439: as R33 on sheet 05 - Processor IO Expansions
R99-R105 R117 = RSMT0439: Manufacturer 1: Vishay; Manufacturer Part Number 1: CRCW040210K0JNED; Description_: RES TKF 10k 5% 1/16W SMD 0402; Dev Tools Status: Production; Voltage: 50V; Temperature Coeffcient: 100ppm/C; Power: 1/16W; Populated: DNP
U7 = MIC7407: Manufacturer 1: Microchip Technology; Manufacturer Part Number 1: 24AA025E48T-I/OT; Description_: MCHP MEMORY SERIAL EEPROM 2Kb I2C 24AA025E48T-I/OT SOT-23-6; MAPS Description: 24AA025E48 device, which will be a pre-prog. version of the 24AA024H (DFAX7).; Dev Tools Status: Design; Owner: Ciprian Abramov; MPC: DFAX7TC8XD00; PackingMedia: T/R; TempRange: -40C to +85C; Stage: REL; LeadCount: 6; ForceMinOrderQtyMult: True; MinOrderQty: 50; LeadContent: Pb-FREE; MemorySize: 2K; OpVoltMin: 1.7; OpVoltMax: 5.5; MaxClockFreq: 400 kHz; AddressPins: 3; PageSize_B: 16; WPScheme: Half Array; MemoryOrg: x8; Endurance: 1,000,000; Comments: memory size changed from 2KBits to 2K; Populated: YES
U8 = MIC6216: SQI Serial Flash; Manufacturer 1: Microchip Technology; Manufacturer Part Number 1: SST26VF064B-104I/SM; Description_: MCHP SERIAL FLASH SST26VF064B-104I/SM SOIJ-8; MAPS Description: 64Mb 2.3V TO 3.6V SQI Flash Memory; Dev Tools Status: Production; Owner: Sompoch Loboonlert; MPC: S01027C3XA23; PackingMedia: TUBE; TempRange: -40C to +85C; Stage: REL; LeadCount: 8; PackageWidth: .208in; ForceMinOrderQtyMult: False; MinOrderQty: 0; LeadContent: Pb-FREE; Busmodes: SPI,SDI,SQI; MemorySize: 64Mb; OpVoltMin: 2,3; OpVoltMax: 3,6; MaxClockFreq: 104 MHz; PageSize_B: 256; WPScheme: Full Array; Endurance: 100,000; Populated: YES
U9 = IC1477: Manufacturer 1: Micron Technology Inc.; MCHP-ID: IC1477; Description_: IC MEMORY MT29F4G08ABAEAWP:E TR FLASH 4GBIT TSOP-48; Dev Tools Status: Design; Vin: 2.7 V to 3.6 V; Owner: Ilie Galan; Populated: YES
U10 = IC1476: 2Gb DDR2-800 SDRAM, 128Mb x 16; Manufacturer 1: Winbond Electronics; MCHP-ID: IC1476; Description_: IC MEMORY W972GG6KB-25 SDRAM 2Gb 800MHz WBGA-84; Dev Tools Status: Design; Vin: 1.7V to 1.9V; Owner: Ciprian Abramov; Populated: YES

## Sheet 07 - USB ports.SchDoc
size B; CompanyName: Microchip Technology Inc.; Organization: Microchip Technology; Address1: 2355 West Chandler Blvd.; Address2: Chandler, AZ  85224; Address4: USA; DocumentNumber: 7; SheetNumber: 7; SheetTotal: 13; SheetTitle: USB interfaces

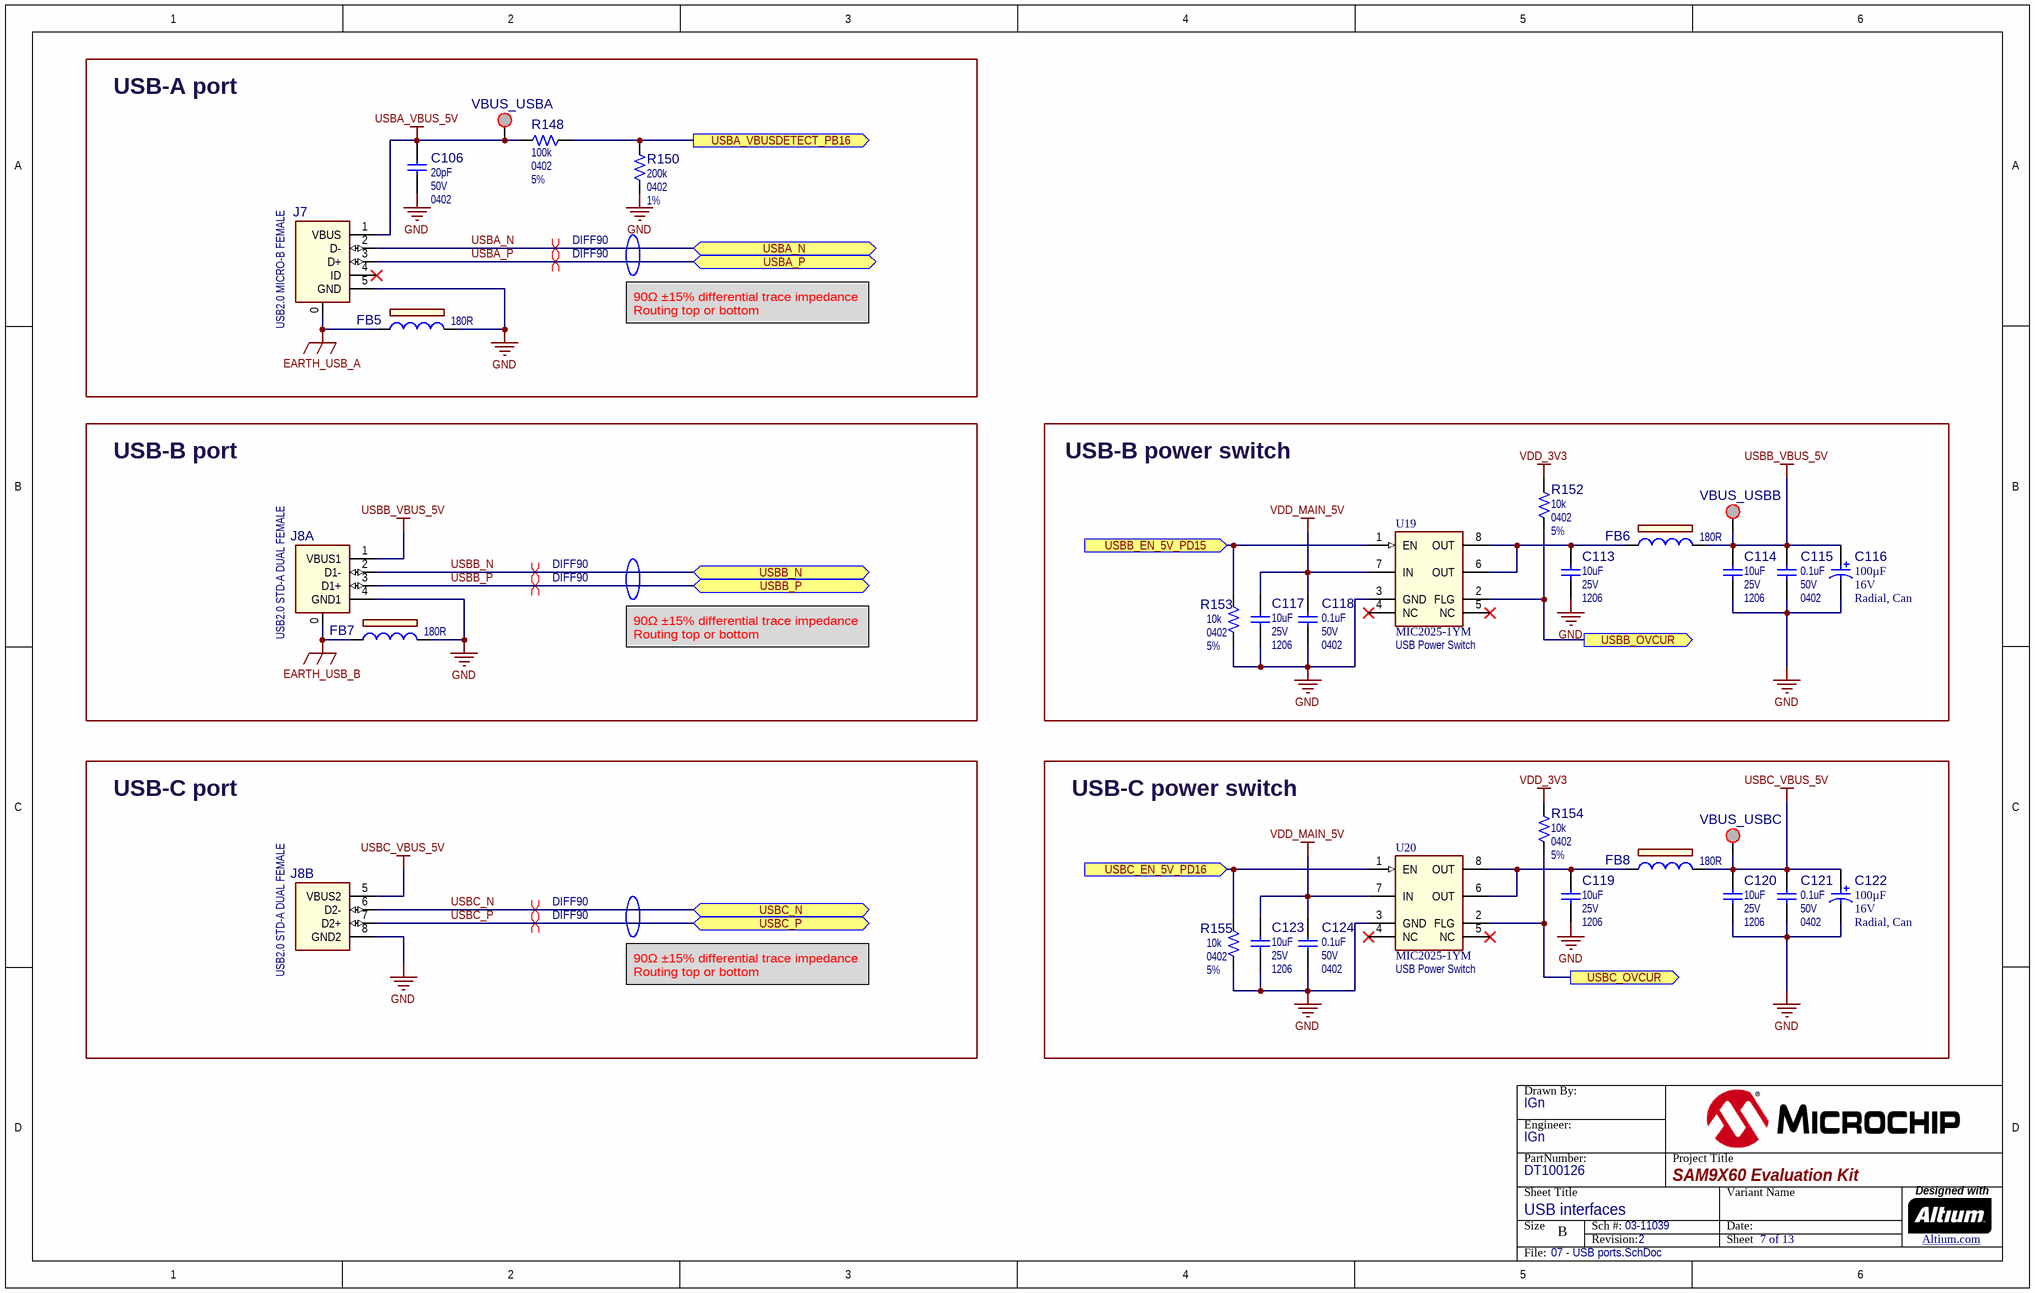
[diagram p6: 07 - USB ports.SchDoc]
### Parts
(Parts that share a designator on the sheet are numbered #1, #2 ... from top to bottom, then left to right.)
?#7  (no value)  (graphical)
C106  value 20pF  Voltage: 50V  Package: 0402  [CAP_C_0402]  (hidden comment: Capacitor NP)
C113  value 10uF  Voltage: 25V  Package: 1206  [CAP_C_1206]  (hidden comment: Capacitor NP)
C114  value 10uF  Voltage: 25V  Package: 1206  [CAP_C_1206]  (hidden comment: Capacitor NP)
C115  value 0.1uF  Voltage: 50V  Package: 0402  [CAP_C_0402]  (hidden comment: Capacitor NP)
C116  value 100µF  Voltage: 16V  Package: Radial, Can  [CAP_RAD_P2D5H12.5]  (hidden comment: Capacitor POL)
C117  value 10uF  Voltage: 25V  Package: 1206  [CAP_C_1206]  (hidden comment: Capacitor NP)
C118  value 0.1uF  Voltage: 50V  Package: 0402  [CAP_C_0402]  (hidden comment: Capacitor NP)
C119  value 10uF  Voltage: 25V  Package: 1206  [CAP_C_1206]  (hidden comment: Capacitor NP)
C120  value 10uF  Voltage: 25V  Package: 1206  [CAP_C_1206]  (hidden comment: Capacitor NP)
C121  value 0.1uF  Voltage: 50V  Package: 0402  [CAP_C_0402]  (hidden comment: Capacitor NP)
C122  value 100µF  Voltage: 16V  Package: Radial, Can  [CAP_RAD_P2D5H12.5]  (hidden comment: Capacitor POL)
C123  value 10uF  Voltage: 25V  Package: 1206  [CAP_C_1206]  (hidden comment: Capacitor NP)
C124  value 0.1uF  Voltage: 50V  Package: 0402  [CAP_C_0402]  (hidden comment: Capacitor NP)
FB5  value 180R  [IND_C_0603]  (hidden comment: Ferrite Bead)
FB6  value 180R  [IND_C_0603]  (hidden comment: Ferrite Bead)
FB7  value 180R  [IND_C_0603]  (hidden comment: Ferrite Bead)
FB8  value 180R  [IND_C_0603]  (hidden comment: Ferrite Bead)
J7  value USB2.0 MICRO-B FEMALE  [CON_USB_Micro-AB_SMD_TH_RA_FCI_10118194-0001LF]  (hidden comment: CON USB2.0 Mini_Micro)
J8  value USB2.0 STD-A DUAL FEMALE  [CON_USB2.0-A_Dual_RCPT_TH_RA_AMN_AU-Y1008-2]  (hidden comment: CON USB2.0 A DUAL)  (parts A,B of 2)
R148  value 100k  Package: 0402  Tolerance: 5%  [RES_C_0402]  (hidden comment: Resistor)
R150  value 200k  Package: 0402  Tolerance: 1%  [RES_C_0402]  (hidden comment: Resistor)
R152  value 10k  Package: 0402  Tolerance: 5%  [RES_C_0402]  (hidden comment: Resistor)
R153  value 10k  Package: 0402  Tolerance: 5%  [RES_C_0402]  (hidden comment: Resistor)
R154  value 10k  Package: 0402  Tolerance: 5%  [RES_C_0402]  (hidden comment: Resistor)
R155  value 10k  Package: 0402  Tolerance: 5%  [RES_C_0402]  (hidden comment: Resistor)
U19  MIC2025-1YM  value USB Power Switch  [SOIC-8]
U20  MIC2025-1YM  value USB Power Switch  [SOIC-8]
VBUS_USBA  SMD Test Point  [TP_1x1_SMD]  (value not drawn)  (no BOM)
VBUS_USBB  SMD Test Point  [TP_1x1_SMD]  (value not drawn)  (no BOM)
VBUS_USBC  SMD Test Point  [TP_1x1_SMD]  (value not drawn)  (no BOM)

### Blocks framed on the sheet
USB-A port: C106 FB5 J7 R148 R150 VBUS_USBA
USB-B port: FB7 J8
USB-B power switch: C113-C118 FB6 R152 R153 U19 VBUS_USBB
USB-C port: J8
USB-C power switch: C119-C124 FB8 R154 R155 U20 VBUS_USBC

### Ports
USBA_N (bidir), USBA_P (bidir), USBA_VBUSDETECT_PB16 (out), USBB_EN_5V_PD15 (in), USBB_N (bidir), USBB_OVCUR (out), USBB_P (bidir), USBC_EN_5V_PD16 (in), USBC_N (bidir), USBC_OVCUR (out), USBC_P (bidir)

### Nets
EARTH_USB_A: FB5.1 J7.0(SHLD)
EARTH_USB_B: FB7.1 J8.0(SHLD)
GND: C106.1 C113.2 C114.2 C115.2 C116.2 C117.2 C118.2 C119.2 C120.2 C121.2 C122.2 C123.2 C124.2 FB5.2 FB7.2 J7.5(GND) J8.4(GND1) J8.8(GND2) R150.1 R153.1 R155.1 U19.3(GND) U20.3(GND)
USBA_VBUS_5V: C106.2 J7.1(VBUS) R148.1 VBUS_USBA.1
USBB_VBUS_5V: C114.1 C115.1 C116.1 FB6.2 J8.1(VBUS1) VBUS_USBB.1
USBC_VBUS_5V: C120.1 C121.1 C122.1 FB8.2 J8.5(VBUS2) VBUS_USBC.1
VDD_3V3: R152.2 R154.2
VDD_MAIN_5V: C117.1 C118.1 C123.1 C124.1 U19.7(IN) U20.7(IN)
USBA_N: J7.2(D-) ; port USBA_N
USBA_P: J7.3(D+) ; port USBA_P
USBA_VBUSDETECT_PB16: R148.2 R150.2 ; port USBA_VBUSDETECT_PB16
USBB_EN_5V_PD15: R153.2 U19.1(EN) ; port USBB_EN_5V_PD15
USBB_N: J8.2(D1-) ; port USBB_N
USBB_OVCUR: R152.1 U19.2(FLG) ; port USBB_OVCUR
USBB_P: J8.3(D1+) ; port USBB_P
USBC_EN_5V_PD16: R155.2 U20.1(EN) ; port USBC_EN_5V_PD16
USBC_N: J8.6(D2-) ; port USBC_N
USBC_OVCUR: R154.1 U20.2(FLG) ; port USBC_OVCUR
USBC_P: J8.7(D2+) ; port USBC_P
NetC113_1: C113.1 FB6.1 U19.6(OUT) U19.8(OUT)
NetC119_1: C119.1 FB8.1 U20.6(OUT) U20.8(OUT)

Not connected (* = marked no-connect by the designer): J7 4(ID)*; U19 4(NC)* 5(NC)*; U20 4(NC)* 5(NC)*

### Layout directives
differential pair; differential pair class DIFF90; net class DIFF90; rule Matched Net Lengths [Tolerance = 10mil]: USBA_N, USBA_P, USBB_N, USBB_P, USBC_N, USBC_P

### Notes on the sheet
- 90Ω ±15% differential trace impedance
  Routing top or bottom

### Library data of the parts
?#7 = Title Block B
C106 = CAP0364: Capacitor; Manufacturer 1: Murata; Manufacturer Part Number 1: GRM1555C1H200JZ01D; Description_: CAP CER 20pF 50V 5% C0G SMD 0402; Dev Tools Status: Production; Tolerance: 5%; Temperature Coeffcient: C0G; Type: Ceramic; Populated: YES
C113 C114 C117 C119 C120 C123 = CAP1418: Capacitor; Manufacturer 1: Samsung Electro-Mechanics America, Inc; Manufacturer Part Number 1: CL31B106KAHNFNE; Description_: CAP CER 10uF 25V 10% X7R SMD 1206; Dev Tools Status: Design; Tolerance: 10%; Temperature Coeffcient: X7R; Type: Ceramic; Populated: YES; Owner: Sorin Stanoaia
C115 C118 C121 C124 = CAP1463: as C53 on sheet 05 - Processor IO Expansions
C116 C122 = CAP1834: Capacitor; Manufacturer 1: Wurth Electronics Inc.; Manufacturer Part Number 1: 860010372006; Description_: CAP 100 UF 20% 16 V; Dev Tools Status: Design; Tolerance: ±20%; Type: Aluminum; Owner: Ed Kennedy; Populated: YES
FB5-FB8 = IND1453: FERRITE 180R 1.5A SMD 0603; Manufacturer 1: Murata Electronics North America; Manufacturer Part Number 1: BLM18PG181SN1D; Dev Tools Status: Production; Owner: Dragos Danaila; DCR: 0.09R; Test Frequency: 100MHz; Populated: YES
J7 = CON1383: Connector USB Mini; Manufacturer 1: FCI; Manufacturer Part Number 1: 10118194-0001LF; Description_: CON USB2.0 MICRO-B FEMALE TH/SMD R/A; Dev Tools Status: Production; Owner: Jamus Griego; Populated: YES
J8 = CON1430: Connector USB DUAL; Manufacturer 1: Assmann WSW Components; Manufacturer Part Number 1: AU-Y1008-2; Description_: CON USB2.0 STD-A DUAL FEMALE TH R/A; Dev Tools Status: Design; Owner: Sorin Stanoaia; Current: 1.5A; Populated: YES
R148 = RES2196: as R34 on sheet 05 - Processor IO Expansions
R150 = RES1424: Manufacturer 1: Panasonic; Manufacturer Part Number 1: ERJ-2RKF2003X; Description_: RES TKF 200k 1% 1/10W SMD 0402; Dev Tools Status: Production; Voltage: 50V; Temperature Coeffcient: 100ppm/C; Power: 1/10W; Owner: Tad Ahlvers; Populated: YES
R152-R155 = RSMT0439: as R33 on sheet 05 - Processor IO Expansions
U19 U20 = MIC7234: Manufacturer 1: Microchip Technology; Dev Tools Status: Production; Owner: Dragos Danaila; Populated: YES
VBUS_USBA VBUS_USBB VBUS_USBC = TEST-POINT: Test Point pad 1.00mm

## Sheet 08 - Ethernet MAC.SchDoc
size B; CompanyName: Microchip Technology Inc.; Organization: Microchip Technology; Address1: 2355 West Chandler Blvd.; Address2: Chandler, AZ  85224; Address4: USA; DocumentNumber: 8; SheetNumber: 8; SheetTotal: 13; SheetTitle: Ethernet MAC

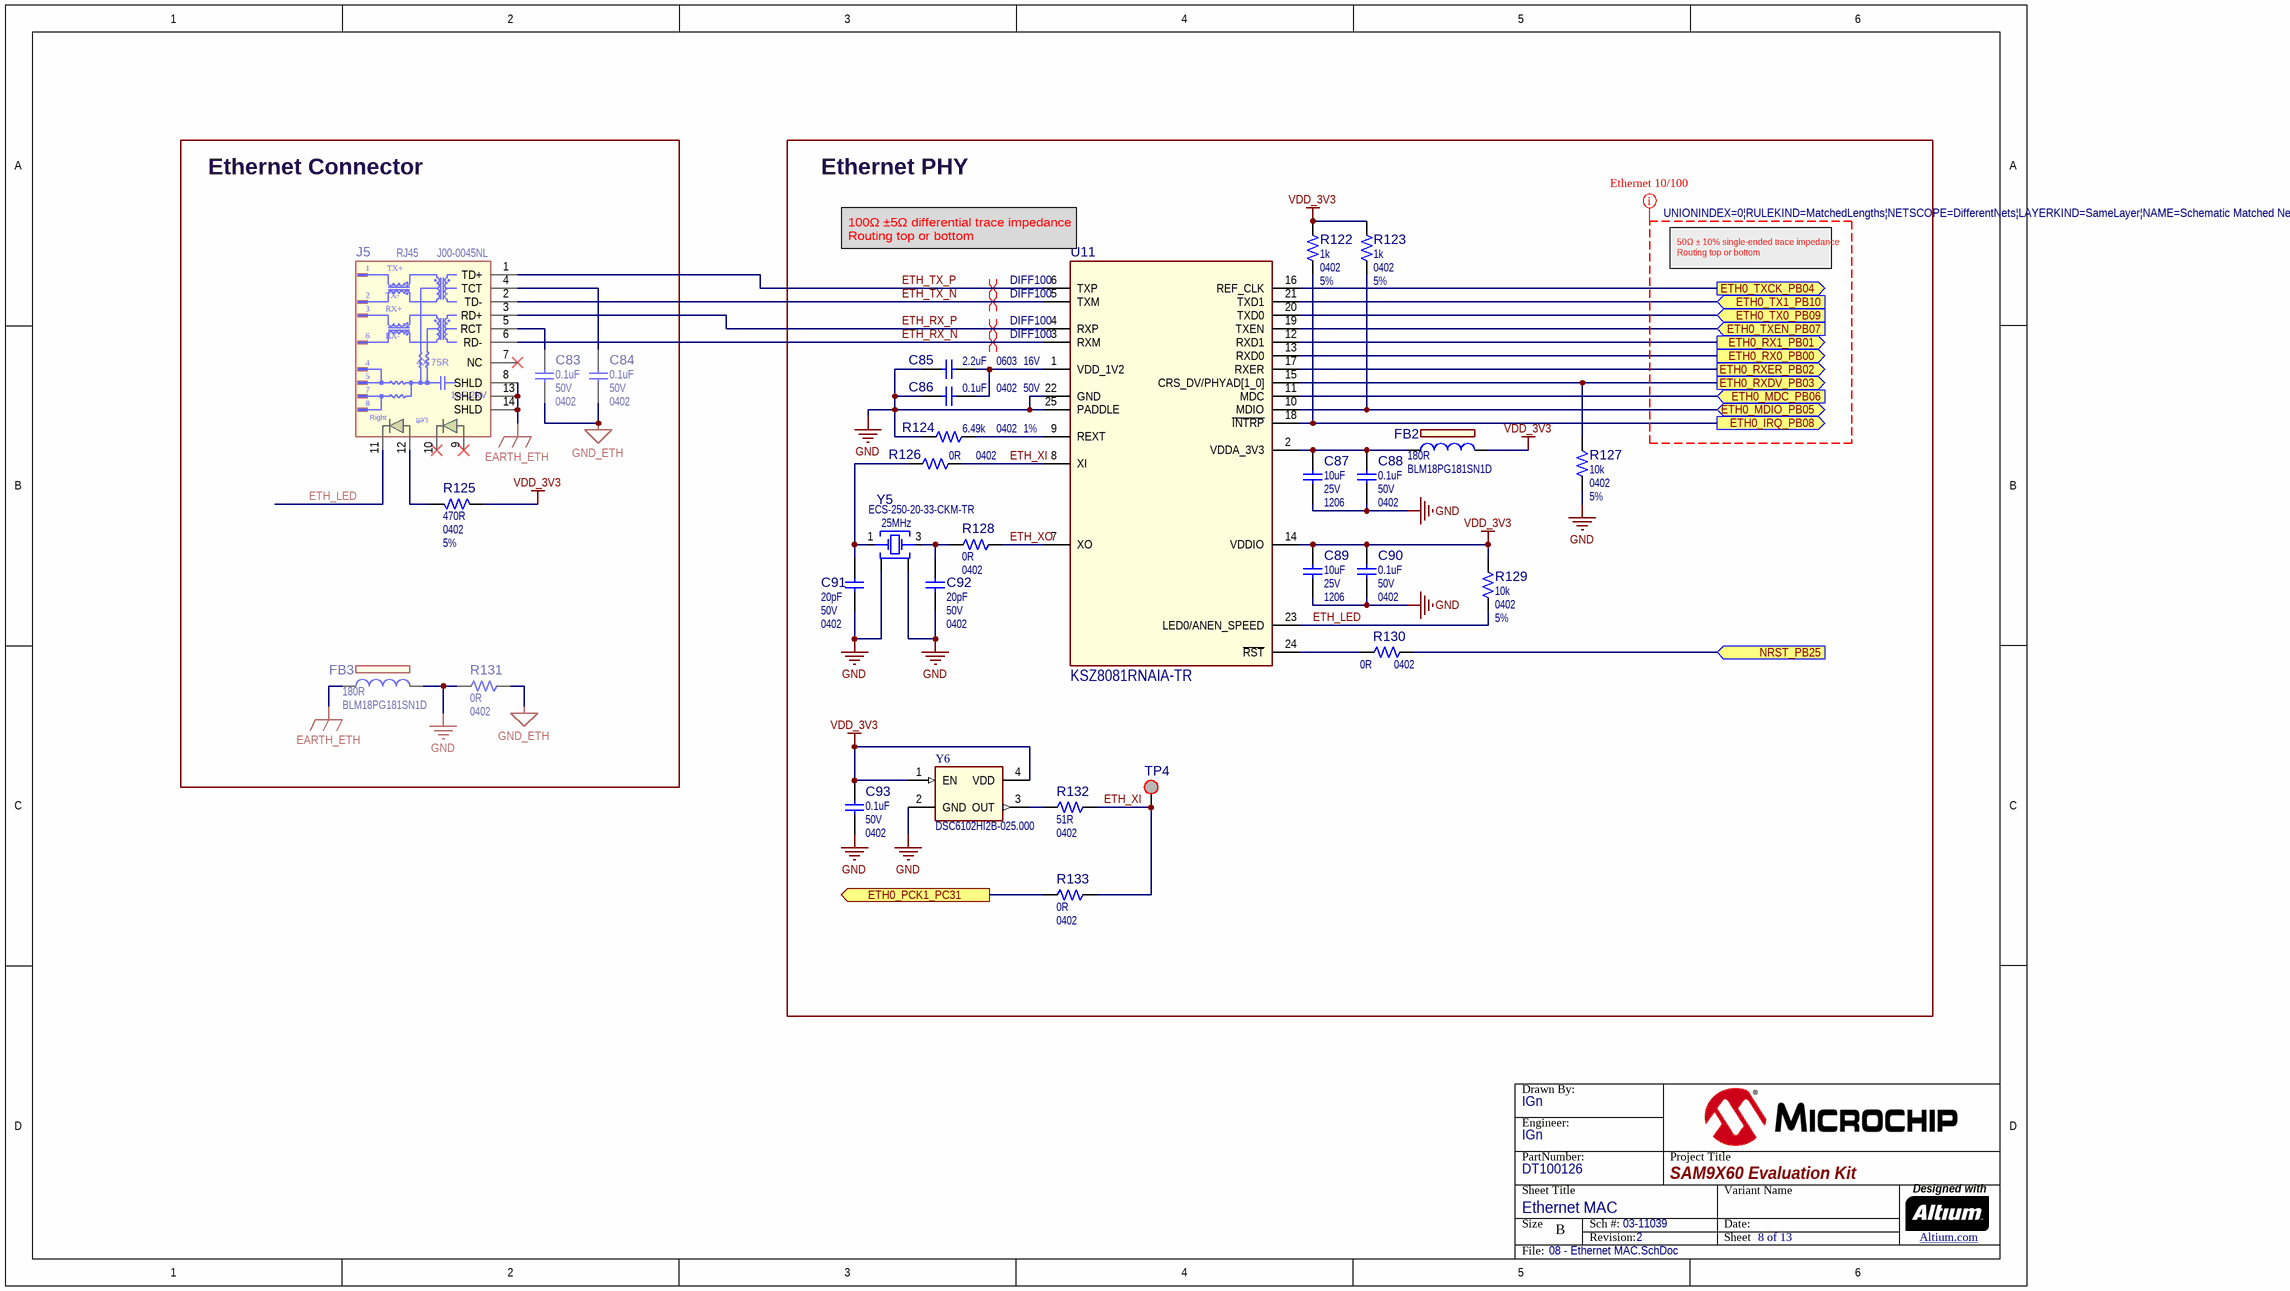
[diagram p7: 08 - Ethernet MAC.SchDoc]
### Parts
(Parts that share a designator on the sheet are numbered #1, #2 ... from top to bottom, then left to right.)
?#8  (no value)  (graphical)
C83  value 0.1uF  Voltage: 50V  Package: 0402  [CAP_C_0402]  (hidden comment: Capacitor NP)
C84  value 0.1uF  Voltage: 50V  Package: 0402  [CAP_C_0402]  (hidden comment: Capacitor NP)
C85  value 2.2uF  Voltage: 16V  Package: 0603  [CAP_C_0603]  (hidden comment: Capacitor NP)
C86  value 0.1uF  Voltage: 50V  Package: 0402  [CAP_C_0402]  (hidden comment: Capacitor NP)
C87  value 10uF  Voltage: 25V  Package: 1206  [CAP_C_1206]  (hidden comment: Capacitor NP)
C88  value 0.1uF  Voltage: 50V  Package: 0402  [CAP_C_0402]  (hidden comment: Capacitor NP)
C89  value 10uF  Voltage: 25V  Package: 1206  [CAP_C_1206]  (hidden comment: Capacitor NP)
C90  value 0.1uF  Voltage: 50V  Package: 0402  [CAP_C_0402]  (hidden comment: Capacitor NP)
C91  value 20pF  Voltage: 50V  Package: 0402  [CAP_C_0402]  (hidden comment: Capacitor NP)
C92  value 20pF  Voltage: 50V  Package: 0402  [CAP_C_0402]  (hidden comment: Capacitor NP)
C93  value 0.1uF  Voltage: 50V  Package: 0402  [CAP_C_0402]  (hidden comment: Capacitor NP)
FB2  value 180R  Manufacturer Part Number 1: BLM18PG181SN1D  [IND_C_0603]  (hidden comment: Ferrite Bead)
FB3  value 180R  Manufacturer Part Number 1: BLM18PG181SN1D  [IND_C_0603]  (hidden comment: Ferrite Bead)
J5  value RJ45  Manufacturer Part Number 1: J00-0045NL  [J00-0045NL_RJ45_connector]  (hidden comment: RJ45 J00-0045NL)
R122  value 1k  Package: 0402  Tolerance: 5%  [RES_C_0402]  (hidden comment: Resistor)
R123  value 1k  Package: 0402  Tolerance: 5%  [RES_C_0402]  (hidden comment: Resistor)
R124  value 6.49k  Package: 0402  Tolerance: 1%  [RES_C_0402]  (hidden comment: Resistor)
R125  value 470R  Package: 0402  Tolerance: 5%  [RES_C_0402]  (hidden comment: Resistor)
R126  value 0R  Package: 0402  [RES_C_0402]  (hidden comment: Resistor)
R127  value 10k  Package: 0402  Tolerance: 5%  [RES_C_0402]  (hidden comment: Resistor)
R128  value 0R  Package: 0402  [RES_C_0402]  (hidden comment: Resistor)
R129  value 10k  Package: 0402  Tolerance: 5%  [RES_C_0402]  (hidden comment: Resistor)
R130  value 0R  Package: 0402  [RES_C_0402]  (hidden comment: Resistor)
R131  value 0R  Package: 0402  [RES_C_0402]  (hidden comment: Resistor)
R132  value 51R  Package: 0402  [RES_C_0402]  (hidden comment: Resistor)
R133  value 0R  Package: 0402  [RES_C_0402]  (hidden comment: Resistor)
TP4  SMD Test Point  [TP_1x1_SMD]  (value not drawn)  (no BOM)
U11  value KSZ8081RNAIA-TR  [QFN-24_4X4]  (hidden comment: ETHERNET QFN-24)
Y5  value 25MHz  Manufacturer Part Number 1: ECS-250-20-33-CKM-TR  [CRYSTAL_L3.2W2.5H0.8]  (hidden comment: Crystal 4 pins 1-3)
Y6  Manufacturer Part Number 1: DSC6102HI2B-025.000  [DFN-4_VFLGA_1.6 X 1.2]  (hidden comment: OSCILLATOR 4 Pins)

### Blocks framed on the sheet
Ethernet Connector: C83 C84 FB3 J5 R125 R131
Ethernet PHY: C85-C93 FB2 R122-R124 R126-R130 R132 R133 TP4 U11 Y5 Y6

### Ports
ETH0_IRQ_PB08 (out), ETH0_MDC_PB06 (in), ETH0_MDIO_PB05 (bidir), ETH0_PCK1_PC31 (out), ETH0_RX0_PB00 (out), ETH0_RX1_PB01 (out), ETH0_RXDV_PB03 (out), ETH0_RXER_PB02 (out), ETH0_TX0_PB09 (in), ETH0_TX1_PB10 (in), ETH0_TXCK_PB04 (out), ETH0_TXEN_PB07 (in), NRST_PB25 (in)

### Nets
EARTH_ETH: FB3.1 J5.8(SHLD) J5.13(SHLD) J5.14(SHLD)
GND: C85.2 C86.2 C87.2 C88.2 C89.2 C90.2 C91.2 C92.2 C93.2 FB3.2 R124.1 R127.2 R131.1 U11.22(GND) U11.25(PADDLE) Y5.2 Y5.4 Y6.2(GND)
GND_ETH: C83.2 C84.2 R131.2
VDD_3V3: C89.1 C90.1 C93.1 FB2.2 R122.1 R123.1 R125.1 R129.1 U11.14(VDDIO) Y6.1(EN) Y6.4(VDD)
ETH0_IRQ_PB08: R122.2 U11.18(~{INTRP}) ; port ETH0_IRQ_PB08
ETH0_MDC_PB06: U11.11(MDC) ; port ETH0_MDC_PB06
ETH0_MDIO_PB05: R123.2 U11.10(MDIO) ; port ETH0_MDIO_PB05
ETH0_PCK1_PC31: R133.2 ; port ETH0_PCK1_PC31
ETH0_RX0_PB00: U11.13(RXD0) ; port ETH0_RX0_PB00
ETH0_RX1_PB01: U11.12(RXD1) ; port ETH0_RX1_PB01
ETH0_RXDV_PB03: R127.1 U11.15(CRS_DV/PHYAD[1_0]) ; port ETH0_RXDV_PB03
ETH0_RXER_PB02: U11.17(RXER) ; port ETH0_RXER_PB02
ETH0_TX0_PB09: U11.20(TXD0) ; port ETH0_TX0_PB09
ETH0_TX1_PB10: U11.21(TXD1) ; port ETH0_TX1_PB10
ETH0_TXCK_PB04: U11.16(REF_CLK) ; port ETH0_TXCK_PB04
ETH0_TXEN_PB07: U11.19(TXEN) ; port ETH0_TXEN_PB07
ETH_LED: J5.11(Ag) R129.2 U11.23(LED0/ANEN_SPEED)
ETH_RX_N: J5.6(RD-) U11.3(RXM)
ETH_RX_P: J5.3(RD+) U11.4(RXP)
ETH_TX_N: J5.2(TD-) U11.5(TXM)
ETH_TX_P: J5.1(TD+) U11.6(TXP)
ETH_XI: R126.1 R132.2 R133.1 TP4.1 U11.8(XI)
ETH_XO: R128.1 U11.7(XO)
NRST_PB25: R130.2 ; port NRST_PB25
NetC83_1: C83.1 J5.5(RCT)
NetC84_1: C84.1 J5.4(TCT)
NetC85_1: C85.1 C86.1 U11.1(VDD_1V2)
NetC87_1: C87.1 C88.1 FB2.1 U11.2(VDDA_3V3)
NetC91_1: C91.1 R126.2 Y5.1
NetC92_1: C92.1 R128.2 Y5.3
NetJ5_12: J5.12(Cg) R125.2
NetR124_2: R124.2 U11.9(REXT)
NetR130_1: R130.1 U11.24(~{RST})
NetR132_1: R132.1 Y6.3(OUT)

Not connected (* = marked no-connect by the designer): J5 7(NC)* 9(Ay)* 10(Cy)*

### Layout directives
net class ETH-RMII; rule Matched Net Lengths [Tolerance = 0.5mm]: (no net found under the mark)
differential pair; differential pair class DIFF100; net class DIFF100; rule Matched Net Lengths [Tolerance = 10mil]: ETH_RX_N, ETH_RX_P, ETH_TX_N, ETH_TX_P

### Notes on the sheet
- (near U11) 100Ω ±5Ω differential trace impedance
  Routing top or bottom
- 50Ω ± 10% single-ended trace impedance
  Routing top or bottom

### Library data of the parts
?#8 = Title Block B
C83 C84 C86 C88 C90 C93 = CAP1463: as C53 on sheet 05 - Processor IO Expansions
C85 = CAP0597: Capacitor; Manufacturer 1: TDK; Manufacturer Part Number 1: C1608X5R1C225K; Description_: CAP CER 2.2uF 16V 10% X5R SMD 0603; Dev Tools Status: Production; Tolerance: 10%; Temperature Coeffcient: X5R; Type: Ceramic; Populated: Yes
C87 C89 = CAP1418: as C113 on sheet 07 - USB ports
C91 C92 = CAP0364: Capacitor; Manufacturer 1: Murata; Manufacturer Part Number 1: GRM1555C1H200JZ01D; Description_: CAP CER 20pF 50V 5% C0G SMD 0402; Dev Tools Status: Production; Tolerance: 5%; Temperature Coeffcient: C0G; Type: Ceramic; Populated: DNP
FB2 FB3 = IND1453: Manufacturer 1: Murata Electronics North America; Description_: FERRITE 180R 1.5A SMD 0603; Dev Tools Status: Design; Owner: Dragos Danaila; DCR: 0.09R; Saturation Current: 1.5A; Test Frequency: 100MHz; Populated: YES
J5 = CON1769: Manufacturer 1: Pulse Electronics Network; Description_: CON MODULAR RJ45 ETHERNET J00-0045NL; Dev Tools Status: Design; Owner: Ilie Galan; Populated: YES
R122 R123 = RSMT0316: Manufacturer 1: Panasonic; Manufacturer Part Number 1: ERJ-2GEJ102X; Description_: RES TKF 1k 5% 1/16W SMD 0402; Dev Tools Status: Production; Voltage: 50V; Temperature Coeffcient: 200ppm/C; Power: 1/16W; Owner: Tad Ahlvers; Populated: YES
R124 = RES1731: Manufacturer 1: Yageo; Manufacturer Part Number 1: RC0402FR-076K49L; Description_: RES TKF 6.49k 1% 1/16W SMD 0402; Dev Tools Status: Production; Voltage: 50V; Temperature Coeffcient: 100ppm/C; Power: 1/16W; Owner: Jesus Aviles; Populated: YES
R125 = RSMT1037: Manufacturer 1: Yageo; Manufacturer Part Number 1: RC0402JR-07470RL; Description_: RES TKF 470R 5% 1/16W SMD 0402; Dev Tools Status: Production; Voltage: 50V; Temperature Coeffcient: 100ppm/C; Power: 1/16W; Owner: Sompoch Loboonlert; Populated: Yes
R126 R128 R133 = RSMT1040: Manufacturer 1: Yageo; Manufacturer Part Number 1: RC0402JR-070RL; Description_: RES TKF 0R 1/16W SMD 0402; Dev Tools Status: Production; Power: 1/16W; Owner: Sompoch Loboonlert; Populated: DNP
R127 R129 = RSMT0439: as R33 on sheet 05 - Processor IO Expansions
R130 R131 = RSMT1040: Manufacturer 1: Yageo; Manufacturer Part Number 1: RC0402JR-070RL; Description_: RES TKF 0R 1/16W SMD 0402; Dev Tools Status: Production; Power: 1/16W; Owner: Sompoch Loboonlert; Populated: Yes
R132 = RSMT1243: Manufacturer 1: Yageo; Manufacturer Part Number 1: RC0402FR-0751RL; Tolerance: 1%; Description_: RES TKF 51R 1% 1/16W SMD 0402; Dev Tools Status: Design; Voltage: 100V; Temperature Coeffcient: 100ppm/C; Current: 1A; Power: 1/16W; Owner: Ciprian Abramov; Populated: YES
TP4 = TEST-POINT: Test Point pad 1.00mm
U11 = MIC7404: Manufacturer 1: Microchip Technology; Description_: MCHP INTERFACE ETHERNET KSZ8081RNAIA-TR QFN-24; Dev Tools Status: Design; Owner: Ciprian Abramov; Populated: YES
Y5 = OSC1159: Crystal; Manufacturer 1: ECS Inc.; Description_: CRYSTAL 25MHz 20pF SMD L3.2W2.5H0.8; Dev Tools Status: Design; Owner: Ciprian Abramov; Tolerance: 10ppm; Load Capacitance: 20pF; Populated: DNP
Y6 = MIC8785: Manufacturer 1: Microchip Technology Inc; Description_: OSCILLATOR MEMS 25MHz DSC6102HI2B-025.000 SMD VFLGA-4; Dev Tools Status: Design; Value: DSC6102HI2B-025.000; Owner: Dragos Danaila; Populated: YES

## Sheet 09 - Wi-Fi BT module.SchDoc
size B; CompanyName: Microchip Technology Inc.; Organization: Microchip Technology; Address1: 2355 West Chandler Blvd.; Address2: Chandler, AZ  85224; Address4: USA; DocumentNumber: 9; SheetNumber: 9; SheetTotal: 13; SheetTitle: Wi-Fi BT

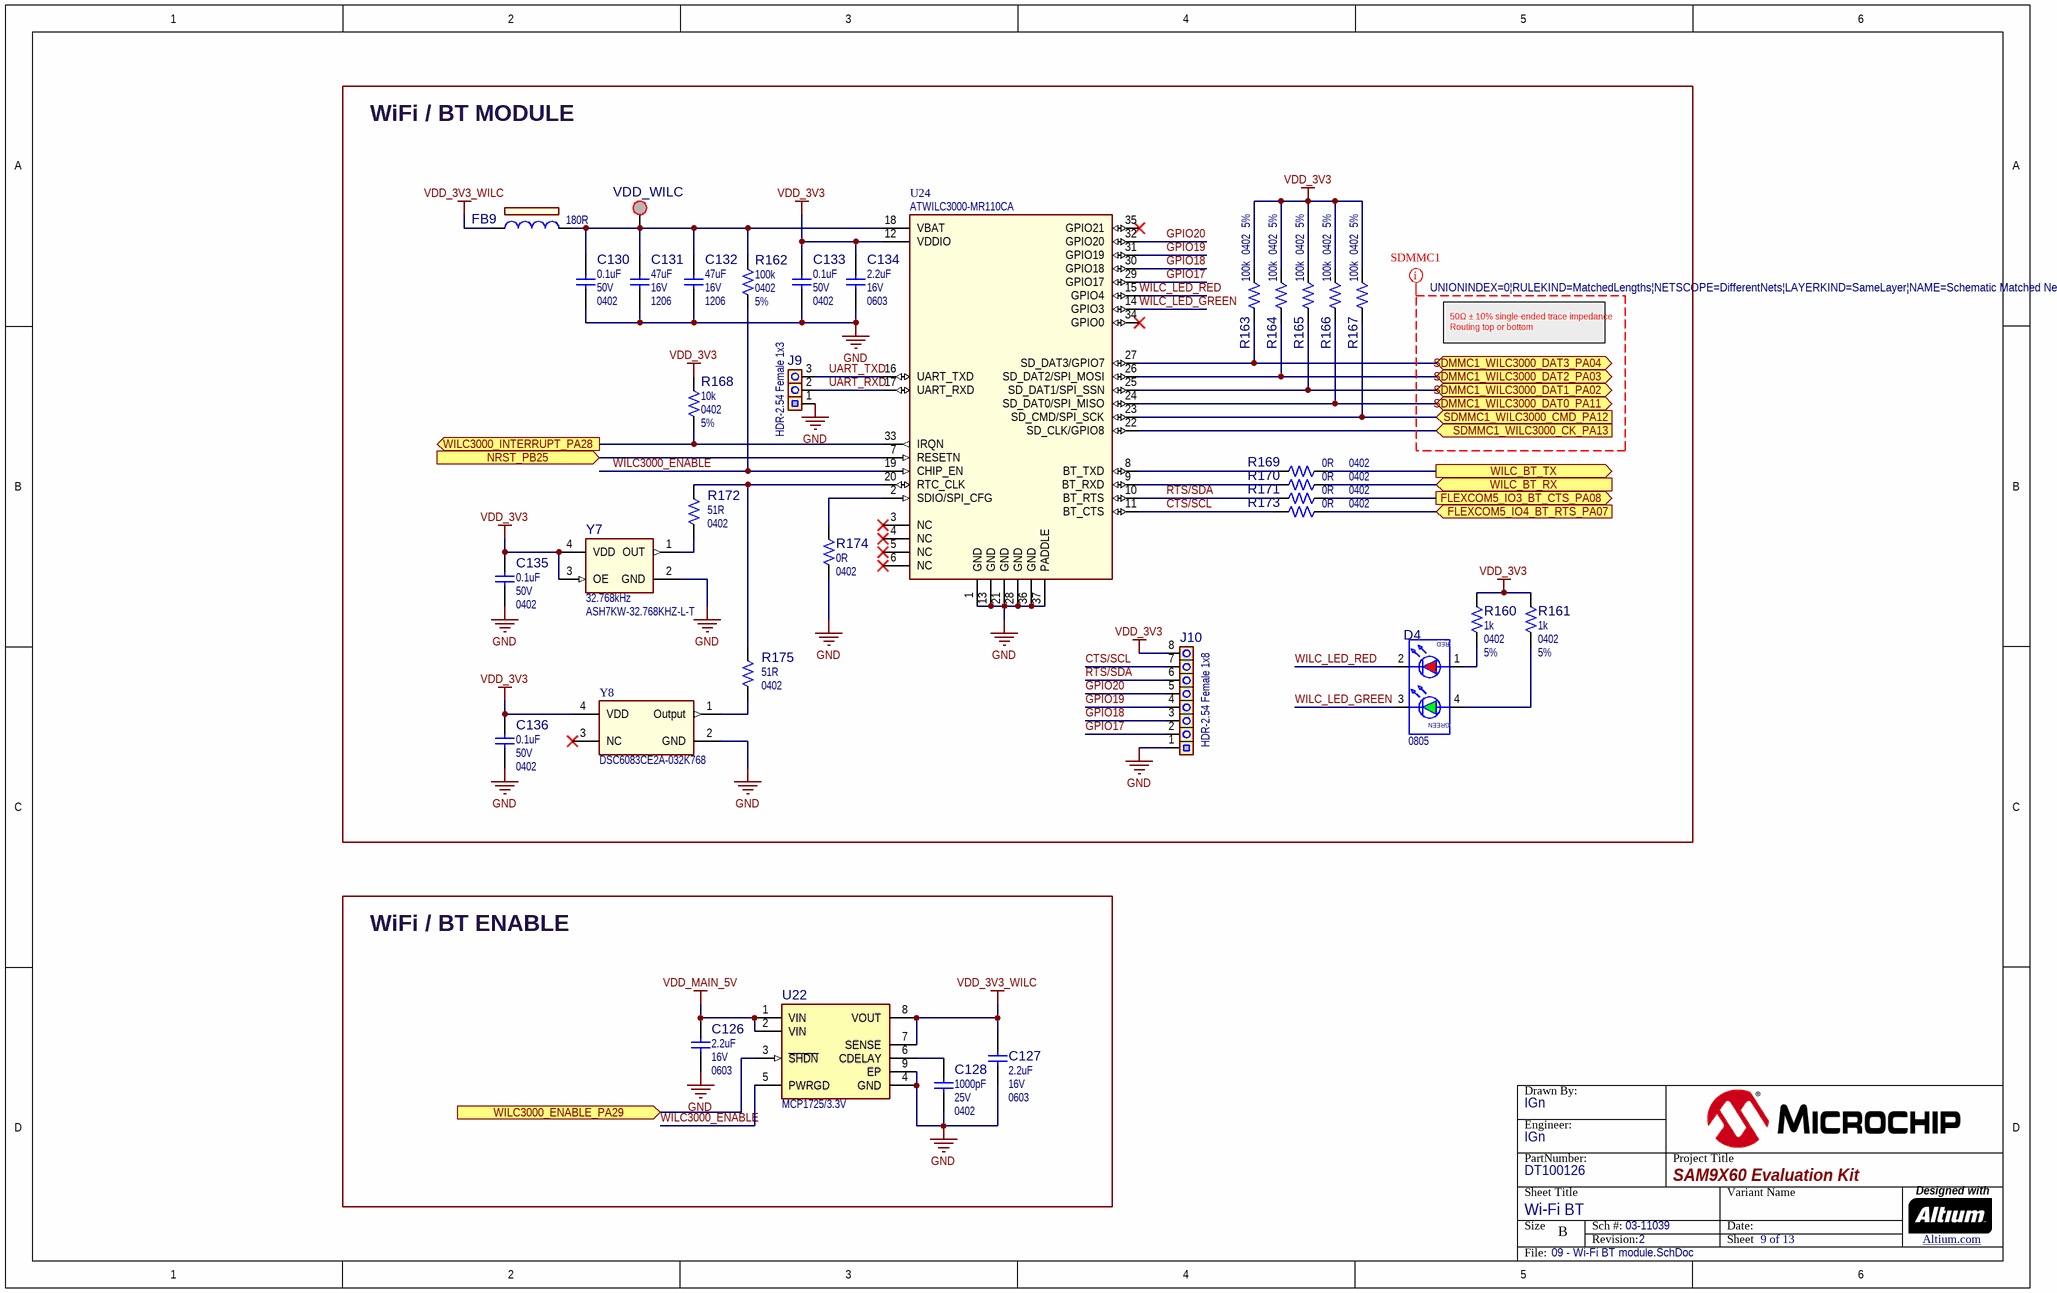
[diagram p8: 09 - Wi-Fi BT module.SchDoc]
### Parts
(Parts that share a designator on the sheet are numbered #1, #2 ... from top to bottom, then left to right.)
?#9  (no value)  (graphical)
C126  value 2.2uF  Voltage: 16V  Package: 0603  [CAP_C_0603]  (hidden comment: Capacitor NP)
C127  value 2.2uF  Voltage: 16V  Package: 0603  [CAP_C_0603]  (hidden comment: Capacitor NP)
C128  value 1000pF  Voltage: 25V  Package: 0402  [CAP_C_0402]  (hidden comment: Capacitor NP)
C130  value 0.1uF  Voltage: 50V  Package: 0402  [CAP_C_0402]  (hidden comment: Capacitor NP)
C131  value 47uF  Voltage: 16V  Package: 1206  [CAP_C_1206]  (hidden comment: Capacitor NP)
C132  value 47uF  Voltage: 16V  Package: 1206  [CAP_C_1206]  (hidden comment: Capacitor NP)
C133  value 0.1uF  Voltage: 50V  Package: 0402  [CAP_C_0402]  (hidden comment: Capacitor NP)
C134  value 2.2uF  Voltage: 16V  Package: 0603  [CAP_C_0603]  (hidden comment: Capacitor NP)
C135  value 0.1uF  Voltage: 50V  Package: 0402  [CAP_C_0402]  (hidden comment: Capacitor NP)
C136  value 0.1uF  Voltage: 50V  Package: 0402  [CAP_C_0402]  (hidden comment: Capacitor NP)
D4  Package: 0805  [LED_DUAL_SMD_2x1.25mm]  (hidden comment: LED DUAL 4 pin)
FB9  value 180R  [IND_C_0603]  (hidden comment: Ferrite Bead)
J9  value HDR-2.54 Female 1x3  [HDR_F_2.54_1x3]  (hidden comment: Header 1x3)
J10  value HDR-2.54 Female 1x8  [HDR_F_2.54_1X8]  (hidden comment: Header 1x8)
R160  value 1k  Package: 0402  Tolerance: 5%  [RES_C_0402]  (hidden comment: Resistor)
R161  value 1k  Package: 0402  Tolerance: 5%  [RES_C_0402]  (hidden comment: Resistor)
R162  value 100k  Package: 0402  Tolerance: 5%  [RES_C_0402]  (hidden comment: Resistor)
R163  value 100k  Package: 0402  Tolerance: 5%  [RES_C_0402]  (hidden comment: Resistor)
R164  value 100k  Package: 0402  Tolerance: 5%  [RES_C_0402]  (hidden comment: Resistor)
R165  value 100k  Package: 0402  Tolerance: 5%  [RES_C_0402]  (hidden comment: Resistor)
R166  value 100k  Package: 0402  Tolerance: 5%  [RES_C_0402]  (hidden comment: Resistor)
R167  value 100k  Package: 0402  Tolerance: 5%  [RES_C_0402]  (hidden comment: Resistor)
R168  value 10k  Package: 0402  Tolerance: 5%  [RES_C_0402]  (hidden comment: Resistor)
R169  value 0R  Package: 0402  [RES_C_0402]  (hidden comment: Resistor)
R170  value 0R  Package: 0402  [RES_C_0402]  (hidden comment: Resistor)
R171  value 0R  Package: 0402  [RES_C_0402]  (hidden comment: Resistor)
R172  value 51R  Package: 0402  [RES_C_0402]  (hidden comment: Resistor)
R173  value 0R  Package: 0402  [RES_C_0402]  (hidden comment: Resistor)
R174  value 0R  Package: 0402  [RES_C_0402]  (hidden comment: Resistor)
R175  value 51R  Package: 0402  [RES_C_0402]  (hidden comment: Resistor)
U22  value MCP1725/3.3V  [DFN-8_2x3]  (hidden comment: MCP172X FIX DFN-8)
U24  value ATWILC3000-MR110CA  [MODULE ATWILC3000-MR110CA]  (hidden comment: MODULE ATWILC3000-MR110CA)
VDD_WILC  SMD Test Point  [TP_1x1_SMD]  (value not drawn)  (no BOM)
Y7  value 32.768kHz  Manufacturer Part Number 1: ASH7KW-32.768KHZ-L-T  [OSCILLATOR_ASH7KW_L3.2W1.5H1]  (hidden comment: OSCILLATOR ASH7KW)
Y8  Manufacturer Part Number 1: DSC6083CE2A-032K768  [OSCILLATOR_DSC1001_L3.2W2.5H0.85]  (hidden comment: OSC_DSC6083CE2A_3225)

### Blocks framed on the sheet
WiFi / BT MODULE: C130-C136 D4 FB9 J9 J10 R160-R175 U24 VDD_WILC Y7 Y8
WiFi / BT ENABLE: C126-C128 U22

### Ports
FLEXCOM5_IO3_BT_CTS_PA08 (out), FLEXCOM5_IO4_BT_RTS_PA07 (in), NRST_PB25 (in), SDMMC1_WILC3000_CK_PA13 (in), SDMMC1_WILC3000_CMD_PA12 (in), SDMMC1_WILC3000_DAT0_PA11 (bidir), SDMMC1_WILC3000_DAT1_PA02 (bidir), SDMMC1_WILC3000_DAT2_PA03 (bidir), SDMMC1_WILC3000_DAT3_PA04 (bidir), WILC3000_ENABLE_PA29 (in), WILC3000_INTERRUPT_PA28 (out), WILC_BT_RX (in), WILC_BT_TX (out)

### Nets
GND: C126.2 C127.1 C128.1 C130.2 C131.2 C132.2 C133.2 C134.1 C135.2 C136.2 J9.1 J10.1 R174.2 U22.4(GND) U22.9(EP) U24.1(GND) U24.13(GND) U24.21(GND) U24.28(GND) U24.36(GND) U24.37(PADDLE) Y7.2(GND) Y8.2(GND)
VDD_3V3: C133.1 C134.2 C135.1 C136.1 J10.8 R160.2 R161.2 R163.2 R164.2 R165.2 R166.2 R167.2 R168.2 U24.12(VDDIO) Y7.3(OE) Y7.4(VDD) Y8.4(VDD)
VDD_3V3_WILC: C127.2 FB9.1 U22.7(SENSE) U22.8(VOUT)
VDD_MAIN_5V: C126.1 U22.1(VIN) U22.2(VIN)
CTS/SCL: J10.7 R173.1 U24.11(BT_CTS)
FLEXCOM5_IO3_BT_CTS_PA08: R171.2 ; port FLEXCOM5_IO3_BT_CTS_PA08
FLEXCOM5_IO4_BT_RTS_PA07: R173.2 ; port FLEXCOM5_IO4_BT_RTS_PA07
GPIO17: J10.2 U24.29(GPIO17)
GPIO18: J10.3 U24.30(GPIO18)
GPIO19: J10.4 U24.31(GPIO19)
GPIO20: J10.5 U24.32(GPIO20)
NRST_PB25: U24.7(RESETN) ; port NRST_PB25
RTS/SDA: J10.6 R171.1 U24.10(BT_RTS)
SDMMC1_WILC3000_CK_PA13: U24.22(SD_CLK/GPIO8) ; port SDMMC1_WILC3000_CK_PA13
SDMMC1_WILC3000_CMD_PA12: R167.1 U24.23(SD_CMD/SPI_SCK) ; port SDMMC1_WILC3000_CMD_PA12
SDMMC1_WILC3000_DAT0_PA11: R166.1 U24.24(SD_DAT0/SPI_MISO) ; port SDMMC1_WILC3000_DAT0_PA11
SDMMC1_WILC3000_DAT1_PA02: R165.1 U24.25(SD_DAT1/SPI_SSN) ; port SDMMC1_WILC3000_DAT1_PA02
SDMMC1_WILC3000_DAT2_PA03: R164.1 U24.26(SD_DAT2/SPI_MOSI) ; port SDMMC1_WILC3000_DAT2_PA03
SDMMC1_WILC3000_DAT3_PA04: R163.1 U24.27(SD_DAT3/GPIO7) ; port SDMMC1_WILC3000_DAT3_PA04
UART_RXD: J9.2 U24.17(UART_RXD)
UART_TXD: J9.3 U24.16(UART_TXD)
WILC3000_ENABLE: R162.1 U22.5(PWRGD) U24.19(CHIP_EN)
WILC3000_ENABLE_PA29: U22.3(~{SHDN}) ; port WILC3000_ENABLE_PA29
WILC3000_INTERRUPT_PA28: R168.1 U24.33(IRQN) ; port WILC3000_INTERRUPT_PA28
WILC_BT_RX: R170.2 ; port WILC_BT_RX
WILC_BT_TX: R169.2 ; port WILC_BT_TX
WILC_LED_GREEN: D4.3(K2) U24.14(GPIO3)
WILC_LED_RED: D4.2(K1) U24.15(GPIO4)
NetC128_2: C128.2 U22.6(CDELAY)
NetC130_1: C130.1 C131.1 C132.1 FB9.2 R162.2 U24.18(VBAT) VDD_WILC.1
NetD4_1: D4.1(A1) R160.1
NetD4_4: D4.4(A2) R161.1
NetR169_1: R169.1 U24.8(BT_TXD)
NetR170_1: R170.1 U24.9(BT_RXD)
NetR172_1: R172.1 R175.1 U24.20(RTC_CLK)
NetR172_2: R172.2 Y7.1(OUT)
NetR174_1: R174.1 U24.2(SDIO/SPI_CFG)
NetR175_2: R175.2 Y8.1(Output)

Not connected (* = marked no-connect by the designer): U24 3(NC)* 4(NC)* 5(NC)* 6(NC)* 34(GPIO0)* 35(GPIO21)*; Y8 3(NC)*

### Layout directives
net class SDMMC-1; rule Matched Net Lengths [Tolerance = 0.25mm]: (no net found under the mark)

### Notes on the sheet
- 50Ω ± 10% single-ended trace impedance
  Routing top or bottom

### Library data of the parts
?#9 = Title Block B
C126 C127 C134 = CAP0597: as C85 on sheet 08 - Ethernet MAC
C128 = CAP0566: as C81 on sheet 06 - On Board Memories
C130 C133 C136 = CAP1463: as C53 on sheet 05 - Processor IO Expansions
C131 = CAP1331: Capacitor; Manufacturer 1: TDK Corporation; Manufacturer Part Number 1: C3216X5R1C476M160AB; Description_: CAP CER 47uF 16V 20% X5R SMD 1206; Dev Tools Status: Production; Tolerance: 20%; Temperature Coeffcient: X5R; Type: Ceramic; Owner: Bogdan Popescu; Populated: YES
C132 = CAP1331: Capacitor; Manufacturer 1: TDK Corporation; Manufacturer Part Number 1: C3216X5R1C476M160AB; Description_: CAP CER 47uF 16V 20% X5R SMD 1206; Dev Tools Status: Production; Tolerance: 20%; Temperature Coeffcient: X5R; Type: Ceramic; Owner: Bogdan Popescu; Populated: DNP
C135 = CAP1463: Capacitor; Manufacturer 1: TDK Corporation; Manufacturer Part Number 1: C1005X7R1H104K050BB; Description_: CAP CER 0.1uF 50V 10% X7R SMD 0402; Dev Tools Status: Production; Tolerance: 10%; Temperature Coeffcient: X7R; Type: Ceramic; Owner: Jamus Griego; Populated: DNP
D4 = DIODE1110: LED; Manufacturer 1: Kingbright Corp; Manufacturer Part Number 1: APHBM2012SURKCGKC; Value: RED, GREEN; Description_: DIO LED BI RED, GREEN 1.95V, 2.1V 30mA 0805; Dev Tools Status: Production; Type: LED Bicolor; Forward Current: 30mA; Power: 75mW; Reverse Current: 10uA; Owner: Bogdan P (M91398); Populated: Yes
FB9 = IND1453: as FB5 on sheet 07 - USB ports
J9 = CON1425: Manufacturer 1: TE Connectivity AMP Connectors; Manufacturer Part Number 1: 5-534237-1; Description_: CON HDR-2.54 Female 1x3 Gold 8.64MH TH VERT; Dev Tools Status: Production; Owner: Md Khan; Populated: DNP
J10 = CON1363: CON HDR-2.54 Female 1x8 Gold TH; Manufacturer 1: Sullins Connector Solutions; Manufacturer Part Number 1: PPPC081LFBN-RC; Dev Tools Status: Production; Owner: Jamus Griego; Populated: DNP
R160 R161 = RSMT0316: as R122 on sheet 08 - Ethernet MAC
R162 = RES2196: as R34 on sheet 05 - Processor IO Expansions
R163-R167 = RES2196: as R35 on sheet 05 - Processor IO Expansions
R168 = RSMT0439: as R33 on sheet 05 - Processor IO Expansions
R169-R171 R173 R174 = RSMT1040: as R130 on sheet 08 - Ethernet MAC
R172 = RSMT1243: Manufacturer 1: Yageo; Manufacturer Part Number 1: RC0402FR-0751RL; Tolerance: 1%; Description_: RES TKF 51R 1% 1/16W SMD 0402; Dev Tools Status: Design; Voltage: 100V; Temperature Coeffcient: 100ppm/C; Current: 1A; Power: 1/16W; Owner: Ciprian Abramov; Populated: DNP
R175 = RSMT1243: as R132 on sheet 08 - Ethernet MAC
U22 = MIC2599: LDO; Manufacturer 1: Microchip; Manufacturer Part Number 1: MCP1725T-3302E/MC; Description_: MCHP ANALOG LDO 3.3V MCP1725T-3302E/MC DFN-8; MAPS Description: 500MA, LOW VOLTAGE LDO; Dev Tools Status: Production; MPC: GEAH1YB3XA33; LeadContent: Pb-FREE; PackingMedia: T/R; Stage: REL; LeadCount: 8; PackageWidth: 2x3x0.9mm; ForceMinOrderQtyMult: True; MinOrderQty: 1; TempRange: -40C to +125C; tblDeviceFamilyID: 1781; Populated: Yes
U24 = MIC7405: Manufacturer 1: Microchip Technology; Description_: MCHP RF WI-FI 802.11b/g/n ATWILC3000-MR110CA; MAPS Description: SmartConnect WILC3000-MR110CA Module; Dev Tools Status: Design; Owner: Ilie Galan; tblDeviceFamilyID: 11256; FrequencyRange: 2.412-2.472 MHz; MaxSpeedMHz: 0; PowerRX: 84mA (802.11n MCS7); PowerTX: 253mA (802.11n MCS7); Sleep: 1.25uA; Populated: YES
VDD_WILC = TEST-POINT: Test Point pad 1.00mm
Y7 = OSC1187: Manufacturer 1: Abracon LLC; Description_: OSCILLATOR 32.768KHZ 1.2V ~ 5.5V SMD DFN-4; Dev Tools Status: Design; Owner: Ilie Galan; Voltage: 1.2-5.5V; Tolerance: 20ppm; Supply Current: 1.8uA; Populated: DNP
Y8 = MIC7476: Manufacturer 1: Microchip Technology; Description_: MCHP CLOCK OSCILLATOR SINGLE 32.768Hz DSC6083CE2A-032K768 SMD DFN-4; Dev Tools Status: Production; Value: 32.768Hz; Owner: Dragos Danaila; Populated: YES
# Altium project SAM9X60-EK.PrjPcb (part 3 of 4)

## Sheet 10 - SDMMC, CAN & CLASSD.SchDoc
size B; CompanyName: Microchip Technology Inc.; Organization: Microchip Technology; Address1: 2355 West Chandler Blvd.; Address2: Chandler, AZ  85224; Address4: USA; DocumentNumber: 10; SheetNumber: 10; SheetTotal: 13; SheetTitle: SDMMC, CAN & CLASSD

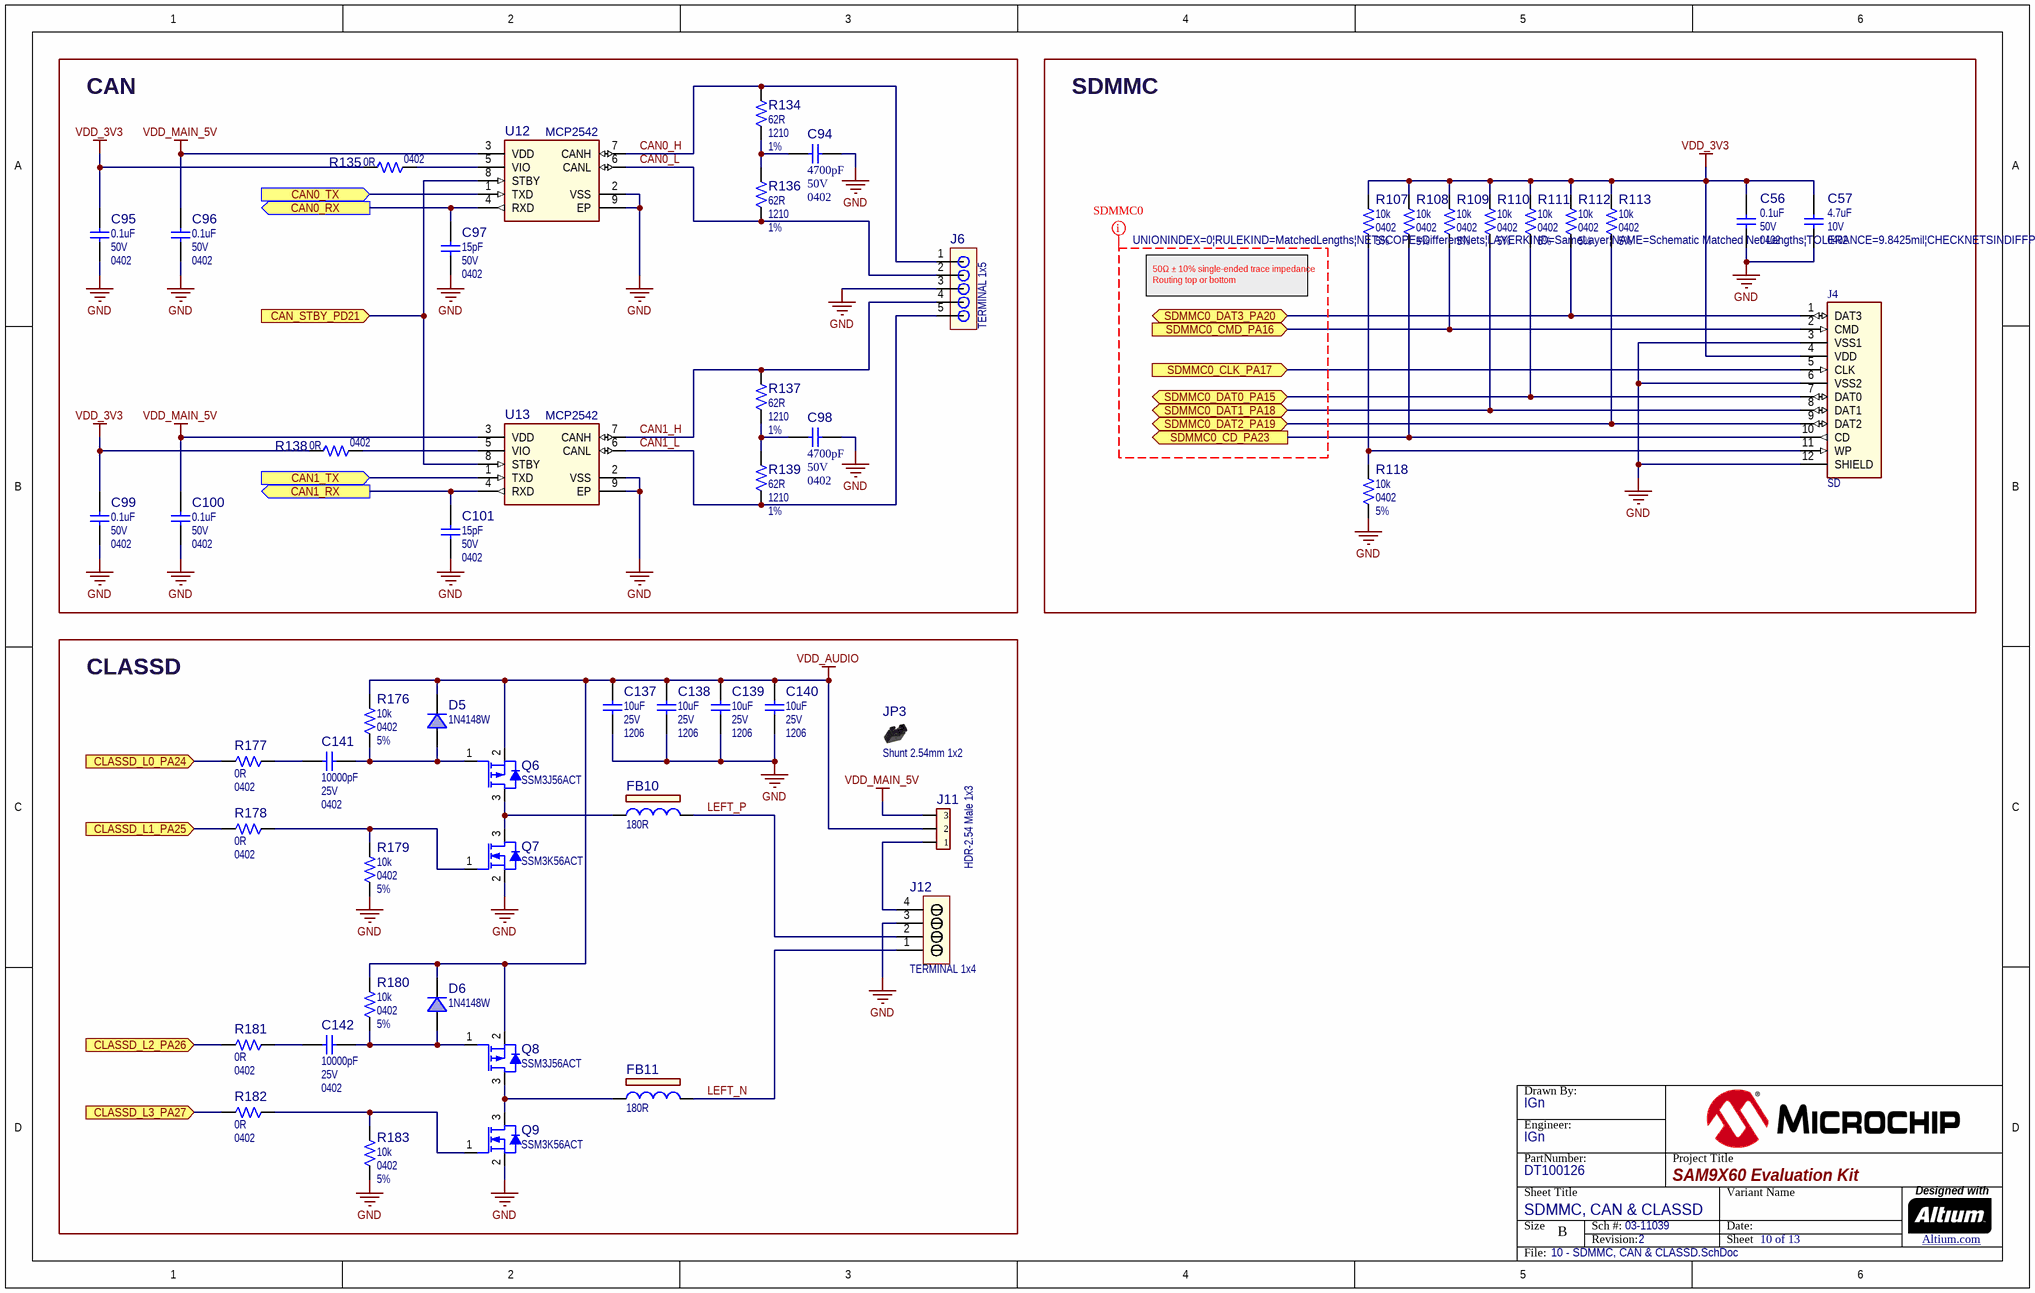
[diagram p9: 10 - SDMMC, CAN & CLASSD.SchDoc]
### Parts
(Parts that share a designator on the sheet are numbered #1, #2 ... from top to bottom, then left to right.)
?#10  (no value)  (graphical)
C56  value 0.1uF  Voltage: 50V  Package: 0402  [CAP_C_0402]  (hidden comment: Capacitor NP)
C57  value 4.7uF  Voltage: 10V  Package: 0402  [CAP_C_0402]  (hidden comment: Capacitor NP)
C94  value 4700pF  Voltage: 50V  Package: 0402  [CAP_C_0402]  (hidden comment: Capacitor NP)
C95  value 0.1uF  Voltage: 50V  Package: 0402  [CAP_C_0402]  (hidden comment: Capacitor NP)
C96  value 0.1uF  Voltage: 50V  Package: 0402  [CAP_C_0402]  (hidden comment: Capacitor NP)
C97  value 15pF  Voltage: 50V  Package: 0402  [CAP_C_0402]  (hidden comment: Capacitor NP)
C98  value 4700pF  Voltage: 50V  Package: 0402  [CAP_C_0402]  (hidden comment: Capacitor NP)
C99  value 0.1uF  Voltage: 50V  Package: 0402  [CAP_C_0402]  (hidden comment: Capacitor NP)
C100  value 0.1uF  Voltage: 50V  Package: 0402  [CAP_C_0402]  (hidden comment: Capacitor NP)
C101  value 15pF  Voltage: 50V  Package: 0402  [CAP_C_0402]  (hidden comment: Capacitor NP)
C137  value 10uF  Voltage: 25V  Package: 1206  [CAP_C_1206]  (hidden comment: Capacitor NP)
C138  value 10uF  Voltage: 25V  Package: 1206  [CAP_C_1206]  (hidden comment: Capacitor NP)
C139  value 10uF  Voltage: 25V  Package: 1206  [CAP_C_1206]  (hidden comment: Capacitor NP)
C140  value 10uF  Voltage: 25V  Package: 1206  [CAP_C_1206]  (hidden comment: Capacitor NP)
C141  value 10000pF  Voltage: 25V  Package: 0402  [CAP_C_0402]  (hidden comment: Capacitor NP)
C142  value 10000pF  Voltage: 25V  Package: 0402  [CAP_C_0402]  (hidden comment: Capacitor NP)
D5  value 1N4148W  [SOD-323]  (hidden comment: Diode Single)
D6  value 1N4148W  [SOD-323]  (hidden comment: Diode Single)
FB10  value 180R  [IND_C_0603]  (hidden comment: Ferrite Bead)
FB11  value 180R  [IND_C_0603]  (hidden comment: Ferrite Bead)
J4  value SD  [10067847-001RLF]  (hidden comment: CON SD CARD 11P_amphenol)
J6  value TERMINAL 1x5  [CON_TERMINAL_3.81_1x5_TH_RA_PHO_1727049]  (hidden comment: CON TERM BLK 1x5 TH Mount)
J11  value HDR-2.54 Male 1x3  [HDR_M_2.54_1x3]  (hidden comment: Header 1x3)
J12  value TERMINAL 1x4  [CON_TERMINAL_2.54_1x4_TH_RA_PHO_1725672]  (hidden comment: Header 1x4)
JP3  value Shunt 2.54mm 1x2  [Jumper_Mechanical]  (hidden comment: Jumper Mechanical)  (mechanical)
Q6  value SSM3J56ACT  [SOT-883]  (hidden comment: Transistor MOS-P GSD)
Q7  value SSM3K56ACT  [SOT-883]  (hidden comment: Transistor MOS-N GSD)
Q8  value SSM3J56ACT  [SOT-883]  (hidden comment: Transistor MOS-P GSD)
Q9  value SSM3K56ACT  [SOT-883]  (hidden comment: Transistor MOS-N GSD)
R107  value 10k  Package: 0402  Tolerance: 5%  [RES_C_0402]  (hidden comment: Resistor)
R108  value 10k  Package: 0402  Tolerance: 5%  [RES_C_0402]  (hidden comment: Resistor)
R109  value 10k  Package: 0402  Tolerance: 5%  [RES_C_0402]  (hidden comment: Resistor)
R110  value 10k  Package: 0402  Tolerance: 5%  [RES_C_0402]  (hidden comment: Resistor)
R111  value 10k  Package: 0402  Tolerance: 5%  [RES_C_0402]  (hidden comment: Resistor)
R112  value 10k  Package: 0402  Tolerance: 5%  [RES_C_0402]  (hidden comment: Resistor)
R113  value 10k  Package: 0402  Tolerance: 5%  [RES_C_0402]  (hidden comment: Resistor)
R118  value 10k  Package: 0402  Tolerance: 5%  [RES_C_0402]  (hidden comment: Resistor)
R134  value 62R  Package: 1210  Tolerance: 1%  [RES_C_1210]  (hidden comment: Resistor)
R135  value 0R  Package: 0402  [RES_C_0402]  (hidden comment: Resistor)
R136  value 62R  Package: 1210  Tolerance: 1%  [RES_C_1210]  (hidden comment: Resistor)
R137  value 62R  Package: 1210  Tolerance: 1%  [RES_C_1210]  (hidden comment: Resistor)
R138  value 0R  Package: 0402  [RES_C_0402]  (hidden comment: Resistor)
R139  value 62R  Package: 1210  Tolerance: 1%  [RES_C_1210]  (hidden comment: Resistor)
R176  value 10k  Package: 0402  Tolerance: 5%  [RES_C_0402]  (hidden comment: Resistor)
R177  value 0R  Package: 0402  [RES_C_0402]  (hidden comment: Resistor)
R178  value 0R  Package: 0402  [RES_C_0402]  (hidden comment: Resistor)
R179  value 10k  Package: 0402  Tolerance: 5%  [RES_C_0402]  (hidden comment: Resistor)
R180  value 10k  Package: 0402  Tolerance: 5%  [RES_C_0402]  (hidden comment: Resistor)
R181  value 0R  Package: 0402  [RES_C_0402]  (hidden comment: Resistor)
R182  value 0R  Package: 0402  [RES_C_0402]  (hidden comment: Resistor)
R183  value 10k  Package: 0402  Tolerance: 5%  [RES_C_0402]  (hidden comment: Resistor)
U12  value MCP2542  [DFN-8_3x3_EP2.4X1.55]  (hidden comment: MCP2542 DFN-8)
U13  value MCP2542  [DFN-8_3x3_EP2.4X1.55]  (hidden comment: MCP2542 DFN-8)

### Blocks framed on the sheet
CAN: C94-C101 J6 R134-R139 U12 U13
SDMMC: C56 C57 J4 R107-R113 R118
CLASSD: C137-C142 D5 D6 FB10 FB11 J11 J12 JP3 Q6-Q9 R176-R183

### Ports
CAN0_RX (out), CAN0_TX (in), CAN1_RX (out), CAN1_TX (in), CAN_STBY_PD21 (in), CLASSD_L0_PA24 (in), CLASSD_L1_PA25 (in), CLASSD_L2_PA26 (in), CLASSD_L3_PA27 (in), SDMMC0_CD_PA23 (out), SDMMC0_CLK_PA17 (in), SDMMC0_CMD_PA16 (in), SDMMC0_DAT0_PA15 (bidir), SDMMC0_DAT1_PA18 (bidir), SDMMC0_DAT2_PA19 (bidir), SDMMC0_DAT3_PA20 (bidir)

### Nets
GND: C56.2 C57.1 C94.1 C95.2 C96.2 C97.1 C98.1 C99.2 C100.2 C101.1 C137.1 C138.1 C139.1 C140.1 J4.3(VSS1) J4.6(VSS2) J4.12(SHIELD) J6.3 J12.3 Q7.2(S) Q9.2(S) R118.1 R179.1 R183.1 U12.2(VSS) U12.9(EP) U13.2(VSS) U13.9(EP)
VDD_3V3: C56.1 C57.2 C95.1 C99.1 J4.4(VDD) R107.2 R108.2 R109.2 R110.2 R111.2 R112.2 R113.2 R135.1 R138.1
VDD_AUDIO: C137.2 C138.2 C139.2 C140.2 D5.2(K) D6.2(K) J11.2 Q6.2(S) Q8.2(S) R176.2 R180.2
VDD_MAIN_5V: C96.1 C100.1 J11.3 U12.3(VDD) U13.3(VDD)
CAN0_H: J6.1 R134.2 U12.7(CANH)
CAN0_L: J6.2 R136.1 U12.6(CANL)
CAN0_RX: C97.2 U12.4(RXD) ; port CAN0_RX
CAN0_TX: U12.1(TXD) ; port CAN0_TX
CAN1_H: J6.4 R137.2 U13.7(CANH)
CAN1_L: J6.5 R139.1 U13.6(CANL)
CAN1_RX: C101.2 U13.4(RXD) ; port CAN1_RX
CAN1_TX: U13.1(TXD) ; port CAN1_TX
CAN_STBY_PD21: U12.8(STBY) U13.8(STBY) ; port CAN_STBY_PD21
CLASSD_L0_PA24: R177.1 ; port CLASSD_L0_PA24
CLASSD_L1_PA25: R178.1 ; port CLASSD_L1_PA25
CLASSD_L2_PA26: R181.1 ; port CLASSD_L2_PA26
CLASSD_L3_PA27: R182.1 ; port CLASSD_L3_PA27
LEFT_N: FB11.2 J12.1
LEFT_P: FB10.2 J12.2
SDMMC0_CD_PA23: J4.10(CD) R108.1 ; port SDMMC0_CD_PA23
SDMMC0_CLK_PA17: J4.5(CLK) ; port SDMMC0_CLK_PA17
SDMMC0_CMD_PA16: J4.2(CMD) R109.1 ; port SDMMC0_CMD_PA16
SDMMC0_DAT0_PA15: J4.7(DAT0) R111.1 ; port SDMMC0_DAT0_PA15
SDMMC0_DAT1_PA18: J4.8(DAT1) R110.1 ; port SDMMC0_DAT1_PA18
SDMMC0_DAT2_PA19: J4.9(DAT2) R113.1 ; port SDMMC0_DAT2_PA19
SDMMC0_DAT3_PA20: J4.1(DAT3) R112.1 ; port SDMMC0_DAT3_PA20
NetC94_2: C94.2 R134.1 R136.2
NetC98_2: C98.2 R137.1 R139.2
NetC141_1: C141.1 R177.2
NetC141_2: C141.2 D5.1(A) Q6.1(G) R176.1
NetC142_1: C142.1 R181.2
NetC142_2: C142.2 D6.1(A) Q8.1(G) R180.1
NetFB10_1: FB10.1 Q6.3(D) Q7.3(D)
NetFB11_1: FB11.1 Q8.3(D) Q9.3(D)
NetJ4_11: J4.11(WP) R107.1 R118.2
NetJ11_1: J11.1 J12.4
NetQ7_1: Q7.1(G) R178.2 R179.2
NetQ9_1: Q9.1(G) R182.2 R183.2
NetR135_2: R135.2 U12.5(VIO)
NetR138_2: R138.2 U13.5(VIO)

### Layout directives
net class SDMMC-0; rule Matched Net Lengths [Tolerance = 0.25mm]: (no net found under the mark)

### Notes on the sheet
- 50Ω ± 10% single-ended trace impedance
  Routing top or bottom

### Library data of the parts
?#10 = Title Block B
C56 = CAP1463: Capacitor; Manufacturer 1: TDK Corporation; Manufacturer Part Number 1: C1005X7R1H104K050BB; Description_: CAP CER 0.1uF 50V 10% X7R SMD 0402; Dev Tools Status: Production; Tolerance: 10%; Temperature Coeffcient: X7R; Type: Ceramic; Populated: YES; Owner: Jamus Griego
C57 = CAP1684: Capacitor; Manufacturer 1: TDK Corporation; Manufacturer Part Number 1: C1005X5R1A475K050BC; Description_: CAP CER 4.7uF 10V 10% X5R SMD 0402; Dev Tools Status: Production; Tolerance: 10%; Temperature Coeffcient: X5R; Type: Ceramic; Owner: Jesus Aviles; Populated: YES
C94 C98 = CAP1391: Capacitor; Manufacturer 1: Murata Electronics North America; Manufacturer Part Number 1: GRM155R71H472KA01D; Description_: CAP CER 4700pF 50V 10% X7R SMD 0402 (Don't Use, Duplicate, use CAP1391); Dev Tools Status: Design; Tolerance: 10%; Temperature Coeffcient: X7R; Type: Ceramic; Owner: Gabor Bihari; Populated: YES
C95 C96 C99 C100 = CAP1463: Capacitor; Manufacturer 1: TDK Corporation; Manufacturer Part Number 1: C1005X7R1H104K050BB; Description_: CAP CER 0.1uF 50V 10% X7R SMD 0402; Dev Tools Status: Production; Tolerance: 10%; Temperature Coeffcient: X7R; Type: Ceramic; Owner: Jamus Griego; Populated: YES
C97 C101 = CAP0608: Capacitor; Manufacturer 1: Murata; Manufacturer Part Number 1: GRM1555C1H150JA01D; Description_: CAP CER 15pF 50V 5% NP0 SMD 0402; Dev Tools Status: Production; Tolerance: 5%; Temperature Coeffcient: NP0; Type: Ceramic; Populated: Yes
C137-C140 = CAP1418: Capacitor; Manufacturer 1: Samsung Electro-Mechanics America, Inc; Manufacturer Part Number 1: CL31B106KAHNFNE; Description_: CAP CER 10uF 25V 10% X7R SMD 1206; Dev Tools Status: Design; Tolerance: 10%; Temperature Coeffcient: X7R; Type: Ceramic; Populated: YES; Owner: Sorin Stanoaia
C141 C142 = CAP0567: Capacitor; Manufacturer 1: TDK; Manufacturer Part Number 1: C1005X7R1E103M; Description_: CAP CER 10000pF 25V 20% X7R SMD 0402; Dev Tools Status: Production; Tolerance: 20%; Temperature Coeffcient: X7R; Type: Ceramic; Populated: YES
D5 D6 = DIODE1102: DIO RECT 1N4148 855mV 300mA 75V SOD-323; Manufacturer 1: Diodes Inc; Manufacturer Part Number 1: 1N4148WS; Description_: DIO RECT 1N4148W 1.25V 150mA 75V SOD-323; Dev Tools Status: Production; Type: Rectifier Single; Forward Current: 150mA; Power: 200mW; Reverse Current: 1uA; Owner: Mihai T(M91442); Populated: Yes
FB10 FB11 = IND1453: FERRITE 180R 1.5A SMD 0603; Manufacturer 1: Murata Electronics North America; Manufacturer Part Number 1: BLM18PG181SN1D; Dev Tools Status: Production; Owner: Dragos Danaila; DCR: 0.09R; Test Frequency: 100MHz; Populated: YES
J4 = CON1752: Manufacturer 1: Amphenol FCI; Description_: 12 (9 + 3) Position Card Connector SD Surface Mount, Right Angle Gold; Dev Tools Status: Design; Owner: Dragos Danaila; Voltage: 17V; Current: 500mA; Populated: YES
J6 = CON1693: Manufacturer 1: Phoenix Contact; Manufacturer Part Number 1: 1727049; Description_: CON TERMINAL 3.81mm 1x5 Female 16-30AWG 13.5A TH R/A; Dev Tools Status: Design; Owner: Ciprian Abramov; Voltage: 300; Current: 13.5A; Populated: YES
J11 = CON0465: Manufacturer 1: Samtec; Manufacturer Part Number 1: TSW-103-07-T-S; Description_: CON HDR-2.54 Male 1x3 Tin 5.84MH TH VERT; Dev Tools Status: Production; Populated: Yes
J12 = CON0005: Manufacturer 1: Phoenix Contact; Manufacturer Part Number 1: 1725672; Description_: CON TERMINAL 2.54mm 1x4 Female 20-30AWG 6A TH R/A; Dev Tools Status: Production; Owner: Sorin Stanoaia; Voltage: 63V; Current: 6A; Populated: YES
JP3 = HW1006: Manufacturer 1: 3M; Manufacturer Part Number 1: 969102-0000-DA; MCHP-ID: HW1006; Description_: MECH HW JUMPER 2.54mm 1x2; Dev Tools Status: Production; Owner: Mike Ragsdale; Populated: MECH
Q6 Q8 = TRA1229: Transistor MOS; Manufacturer 1: Toshiba Semiconductor and Storage; Manufacturer Part Number 1: SSM3J56ACT,L3F; Description_: TRANS FET P-CH SSM3J56ACT 20V 1.4A 0.39R 0.5W SOT-883; Dev Tools Status: Design; Type: FET; Current: 1.4A; Drain to Source Voltage: 20V; Gate to Source Voltage: 8V; Power: 0.5W; Owner: Ciprian Abramov; Populated: YES
Q7 Q9 = TRA1230: Transistor MOS; Manufacturer 1: Toshiba Semiconductor and Storage; Manufacturer Part Number 1: SSM3K56ACT,L3F; Description_: TRANS FET N-CH SSM3K56ACT 20V 1.4A 0.235R 0.5W SOT-883; Dev Tools Status: Design; Type: FET; Current: 1.4A; Drain to Source Voltage: 20V; Gate to Source Voltage: 4.5V; Power: 0.5W; Owner: Ciprian Abramov; Populated: YES
R107 = RSMT0439: Manufacturer 1: Vishay; Manufacturer Part Number 1: CRCW040210K0JNED; Description_: RES TKF 10k 5% 1/16W SMD 0402; Dev Tools Status: Production; Voltage: 50V; Temperature Coeffcient: 100ppm/C; Power: 1/16W; Populated: YES
R108-R113 R176 R179 R180 R183 = RSMT0439: Manufacturer 1: Vishay; Manufacturer Part Number 1: CRCW040210K0JNED; Description_: RES TKF 10k 5% 1/16W SMD 0402; Dev Tools Status: Production; Voltage: 50V; Temperature Coeffcient: 100ppm/C; Power: 1/16W; Populated: Yes
R118 = RSMT0439: Manufacturer 1: Vishay; Manufacturer Part Number 1: CRCW040210K0JNED; Description_: RES TKF 10k 5% 1/16W SMD 0402; Dev Tools Status: Production; Voltage: 50V; Temperature Coeffcient: 100ppm/C; Power: 1/16W; Populated: DNP
R134 R136 R137 R139 = RSMT1222: Manufacturer 1: Yageo; Manufacturer Part Number 1: RC1210FR-0762RL; Description_: RES TKF 62R 1% 1/2W SMD 1210; Dev Tools Status: Production; Voltage: 200V; Temperature Coeffcient: 100PPM/C; Current: 5.56A; Power: 1/2W; Owner: Dragos Danaila; Populated: YES
R135 R138 R177 R178 R181 R182 = RSMT1040: Manufacturer 1: Yageo; Manufacturer Part Number 1: RC0402JR-070RL; Description_: RES TKF 0R 1/16W SMD 0402; Dev Tools Status: Production; Power: 1/16W; Owner: Sompoch Loboonlert; Populated: Yes
U12 U13 = MIC7856: Manufacturer 1: Microchip Technology; Manufacturer Part Number 1: MCP2542FDT-E/MF; Description_: MCHP INTERFACE CAN MCP2542FDT-E/MF DFN-8; MAPS Description: CAN Transceiver; Dev Tools Status: Design; Owner: Ilie Galan; MPC: V7BC6YA7XA00; LeadContent: Pb-FREE; PackingMedia: T/R; Stage: REL; LeadCount: 8; PackageWidth: 3x3x0.9mm; ForceMinOrderQtyMult: True; MinOrderQty: 3300; TempRange: -40C to +125C; tblDeviceFamilyID: 5993; DeviceType: Transceiver; OperatingVoltageMin: 4.5; OperatingVoltageMax: 5.5; StandbyCurrentMax: 15; OperatingCurrentMax: 10; PropDelayMax: 120; ShortCircuit: -58 to +58; TransientVoltage: -150 to +100; ESD: 13; ThermalShutdown: Yes; CMR: +/-12; Masks: 0; Comments: Flexible Data Rate Capable

## Sheet 11 - Expansion connectors.SchDoc
size B; CompanyName: Microchip Technology Inc.; Organization: Microchip Technology; Address1: 2355 West Chandler Blvd.; Address2: Chandler, AZ  85224; Address4: USA; DocumentNumber: 11; SheetNumber: 11; SheetTotal: 13; SheetTitle: Expansion connectors

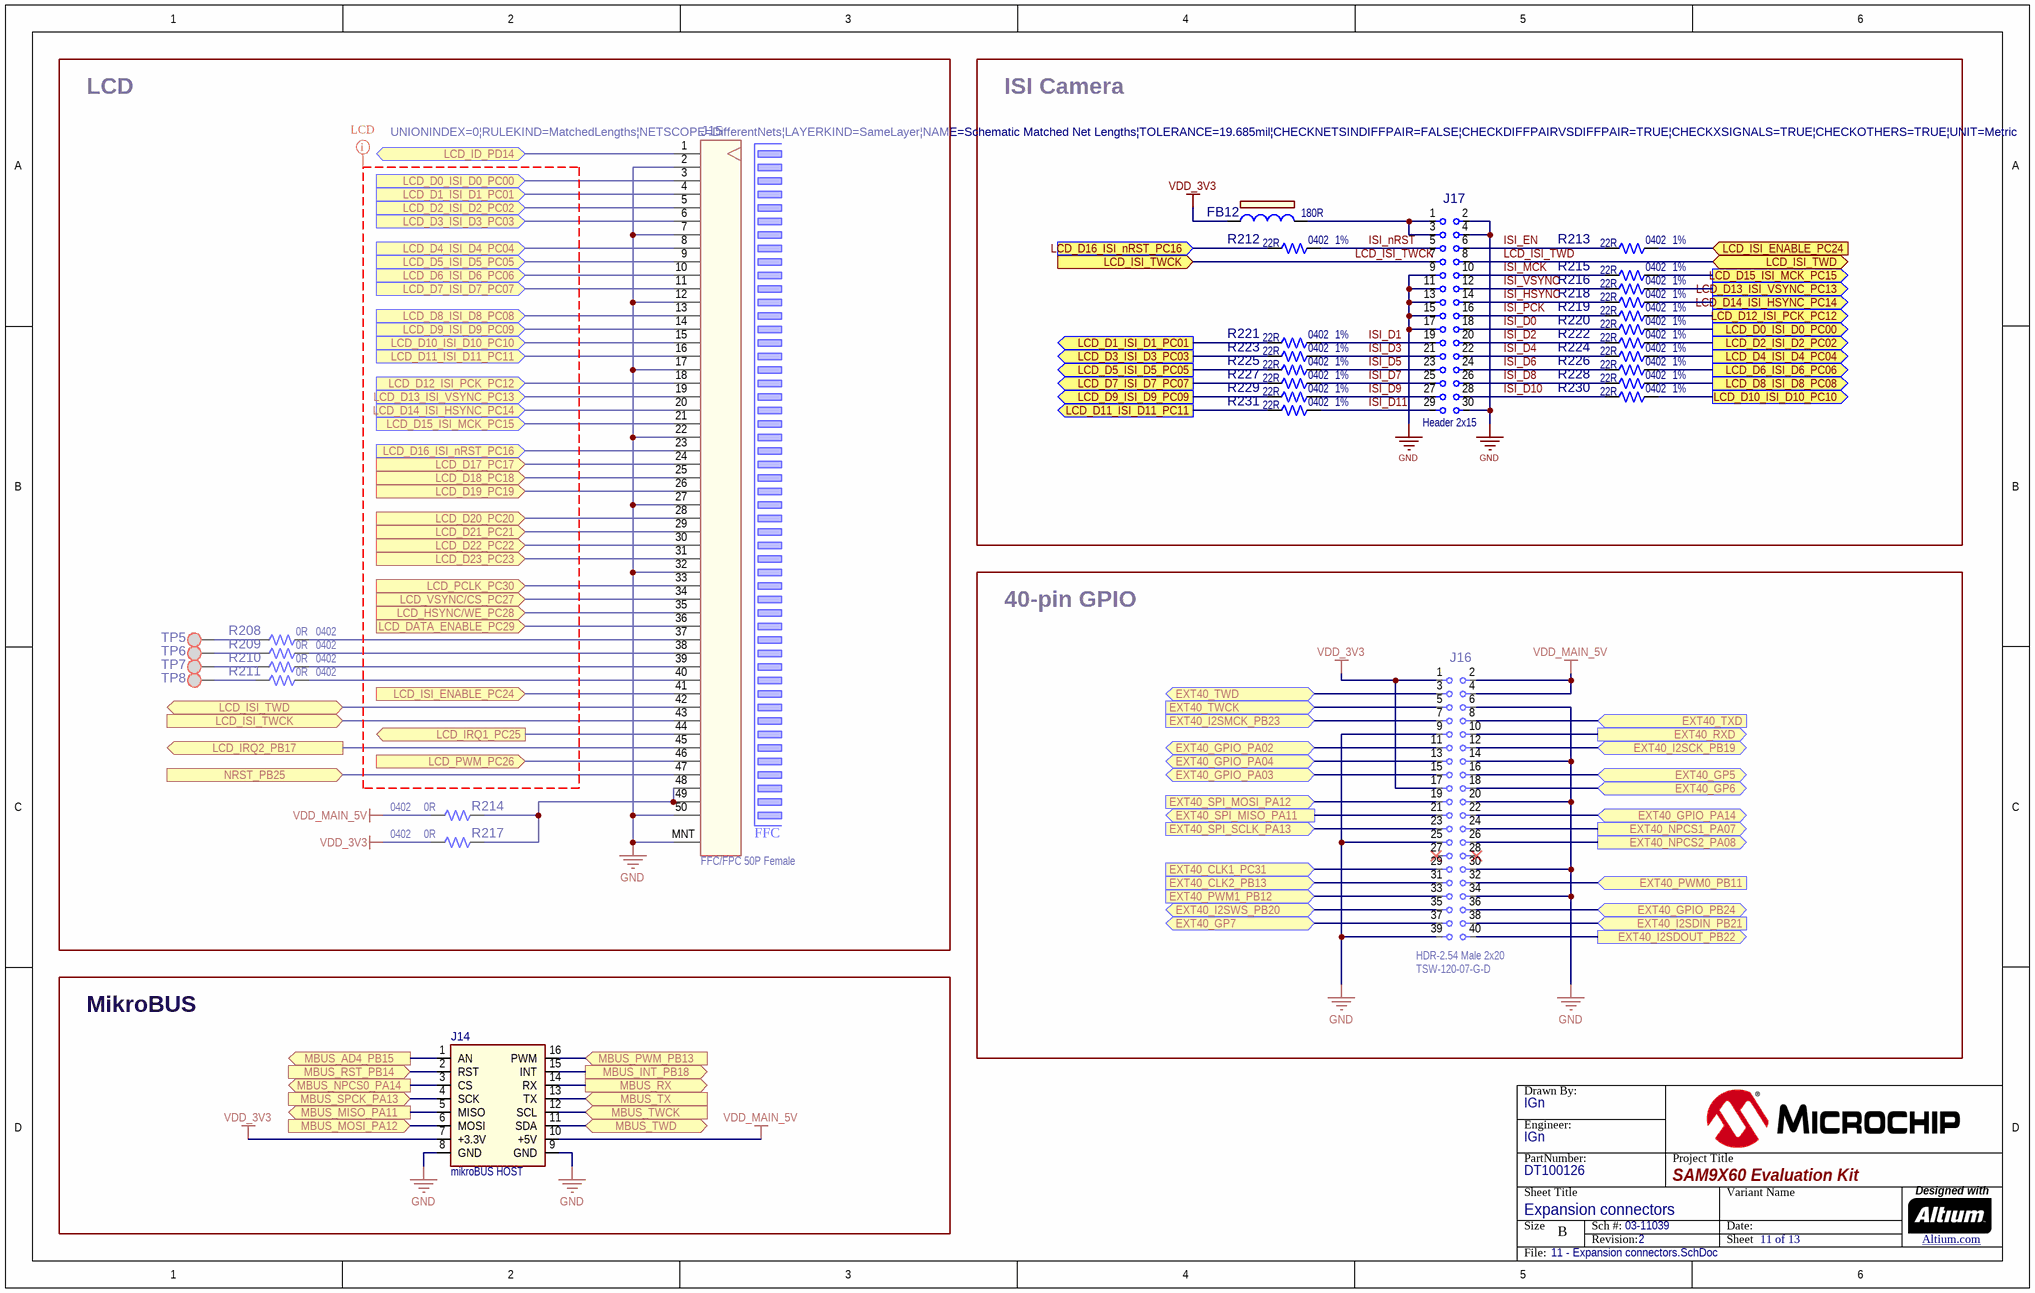
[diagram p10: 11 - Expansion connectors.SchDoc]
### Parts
(Parts that share a designator on the sheet are numbered #1, #2 ... from top to bottom, then left to right.)
?#11  (no value)  (graphical)
FB12  value 180R  [IND_C_0603]  (hidden comment: Ferrite Bead)
J14  value mikroBUS HOST  [SOCKET_mikroBUS_F_2.54_2x8_V_25.4x21]  (hidden comment: SOCKET mikroBUS HOST)
J15  value FFC/FPC 50P Female  [CON_FFC_0.5_FEMALE_1X50_SMD_OMR_XF2M-5015-1A]  (hidden comment: CON FFC 1x50 Mount)
J16  value HDR-2.54 Male 2x20  Manufacturer Part Number 1: TSW-120-07-G-D  [HDR_M_2.54_2x20]  (hidden comment: Header 2x20)
J17  Header 2x15  [HDR_M_2.54_2x15]
R208  value 0R  Package: 0402  [RES_C_0402]  (hidden comment: Resistor)
R209  value 0R  Package: 0402  [RES_C_0402]  (hidden comment: Resistor)
R210  value 0R  Package: 0402  [RES_C_0402]  (hidden comment: Resistor)
R211  value 0R  Package: 0402  [RES_C_0402]  (hidden comment: Resistor)
R212  value 22R  Package: 0402  Tolerance: 1%  [RES_C_0402]  (hidden comment: Resistor)
R213  value 22R  Package: 0402  Tolerance: 1%  [RES_C_0402]  (hidden comment: Resistor)
R214  value 0R  Package: 0402  [RES_C_0402]  (hidden comment: Resistor)
R215  value 22R  Package: 0402  Tolerance: 1%  [RES_C_0402]  (hidden comment: Resistor)
R216  value 22R  Package: 0402  Tolerance: 1%  [RES_C_0402]  (hidden comment: Resistor)
R217  value 0R  Package: 0402  [RES_C_0402]  (hidden comment: Resistor)
R218  value 22R  Package: 0402  Tolerance: 1%  [RES_C_0402]  (hidden comment: Resistor)
R219  value 22R  Package: 0402  Tolerance: 1%  [RES_C_0402]  (hidden comment: Resistor)
R220  value 22R  Package: 0402  Tolerance: 1%  [RES_C_0402]  (hidden comment: Resistor)
R221  value 22R  Package: 0402  Tolerance: 1%  [RES_C_0402]  (hidden comment: Resistor)
R222  value 22R  Package: 0402  Tolerance: 1%  [RES_C_0402]  (hidden comment: Resistor)
R223  value 22R  Package: 0402  Tolerance: 1%  [RES_C_0402]  (hidden comment: Resistor)
R224  value 22R  Package: 0402  Tolerance: 1%  [RES_C_0402]  (hidden comment: Resistor)
R225  value 22R  Package: 0402  Tolerance: 1%  [RES_C_0402]  (hidden comment: Resistor)
R226  value 22R  Package: 0402  Tolerance: 1%  [RES_C_0402]  (hidden comment: Resistor)
R227  value 22R  Package: 0402  Tolerance: 1%  [RES_C_0402]  (hidden comment: Resistor)
R228  value 22R  Package: 0402  Tolerance: 1%  [RES_C_0402]  (hidden comment: Resistor)
R229  value 22R  Package: 0402  Tolerance: 1%  [RES_C_0402]  (hidden comment: Resistor)
R230  value 22R  Package: 0402  Tolerance: 1%  [RES_C_0402]  (hidden comment: Resistor)
R231  value 22R  Package: 0402  Tolerance: 1%  [RES_C_0402]  (hidden comment: Resistor)
TP5  SMD Test Point  [TP_1x1_SMD]  (value not drawn)  (no BOM)
TP6  SMD Test Point  [TP_1x1_SMD]  (value not drawn)  (no BOM)
TP7  SMD Test Point  [TP_1x1_SMD]  (value not drawn)  (no BOM)
TP8  SMD Test Point  [TP_1x1_SMD]  (value not drawn)  (no BOM)

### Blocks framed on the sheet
LCD: J15 R208-R211 R214 R217 TP5-TP8
ISI Camera: FB12 J17 R212 R213 R215 R216 R218-R231
40-pin GPIO: J16
MikroBUS: J14

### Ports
EXT40_CLK1_PC31 (in), EXT40_CLK2_PB13 (in), EXT40_GP5 (bidir), EXT40_GP6 (bidir), EXT40_GP7 (bidir), EXT40_GPIO_PA02 (bidir), EXT40_GPIO_PA03 (bidir), EXT40_GPIO_PA04 (bidir), EXT40_GPIO_PA14 (bidir), EXT40_GPIO_PB24 (bidir), EXT40_I2SCK_PB19 (bidir), EXT40_I2SDIN_PB21 (in), EXT40_I2SDOUT_PB22 (out), EXT40_I2SMCK_PB23 (in), EXT40_I2SWS_PB20 (bidir), EXT40_NPCS1_PA07 (out), EXT40_NPCS2_PA08 (out), EXT40_PWM0_PB11 (in), EXT40_PWM1_PB12 (in), EXT40_RXD (out), EXT40_SPI_MISO_PA11 (out), EXT40_SPI_MOSI_PA12 (in), EXT40_SPI_SCLK_PA13 (in), EXT40_TWCK (in), EXT40_TWD (bidir), EXT40_TXD (in), LCD_D0_ISI_D0_PC00 (in), LCD_D0_ISI_D0_PC00 (out), LCD_D1_ISI_D1_PC01 (in), LCD_D1_ISI_D1_PC01 (out), LCD_D2_ISI_D2_PC02 (in), LCD_D2_ISI_D2_PC02 (out), LCD_D3_ISI_D3_PC03 (in), LCD_D3_ISI_D3_PC03 (out), LCD_D4_ISI_D4_PC04 (in), LCD_D4_ISI_D4_PC04 (out), LCD_D5_ISI_D5_PC05 (in), LCD_D5_ISI_D5_PC05 (out), LCD_D6_ISI_D6_PC06 (in), LCD_D6_ISI_D6_PC06 (out), LCD_D7_ISI_D7_PC07 (in), LCD_D7_ISI_D7_PC07 (out), LCD_D8_ISI_D8_PC08 (in), LCD_D8_ISI_D8_PC08 (out), LCD_D9_ISI_D9_PC09 (in), LCD_D9_ISI_D9_PC09 (out), LCD_D10_ISI_D10_PC10 (in), LCD_D10_ISI_D10_PC10 (out), LCD_D11_ISI_D11_PC11 (in), LCD_D11_ISI_D11_PC11 (out), LCD_D12_ISI_PCK_PC12 (in), LCD_D12_ISI_PCK_PC12 (out), LCD_D13_ISI_VSYNC_PC13 (in), LCD_D13_ISI_VSYNC_PC13 (out), LCD_D14_ISI_HSYNC_PC14 (in), LCD_D14_ISI_HSYNC_PC14 (out), LCD_D15_ISI_MCK_PC15 (in), LCD_D15_ISI_MCK_PC15 (out), LCD_D16_ISI_nRST_PC16 (in), LCD_D17_PC17 (in), LCD_D18_PC18 (in), LCD_D19_PC19 (in), LCD_D20_PC20 (in), LCD_D21_PC21 (in), LCD_D22_PC22 (in), LCD_D23_PC23 (in), LCD_DATA_ENABLE_PC29 (in), LCD_HSYNC/WE_PC28 (in), LCD_ID_PD14 (bidir), LCD_IRQ1_PC25 (out), LCD_IRQ2_PB17 (out), LCD_ISI_ENABLE_PC24 (in), LCD_ISI_TWCK (in), LCD_ISI_TWD (bidir), LCD_PCLK_PC30 (in), LCD_PWM_PC26 (in), LCD_VSYNC/CS_PC27 (in), MBUS_AD4_PB15 (out), MBUS_INT_PB18 (out), MBUS_MISO_PA11 (out), MBUS_MOSI_PA12 (in), MBUS_NPCS0_PA14 (out), MBUS_PWM_PB13 (in), MBUS_RST_PB14 (in), MBUS_RX (out), MBUS_SPCK_PA13 (in), MBUS_TWCK (in), MBUS_TWD (bidir), MBUS_TX (in), NRST_PB25 (in)

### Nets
GND: J14.8(GND) J14.9(GND) J15.2 J15.7 J15.12 J15.17 J15.22 J15.27 J15.32 J15.50 J15.MNT J16.6 J16.9 J16.14 J16.20 J16.25 J16.30 J16.34 J16.39 J17.2 J17.4 J17.9 J17.11 J17.13 J17.15 J17.17 J17.30
VDD_3V3: FB12.1 J14.7(+3.3V) J16.1 J16.17 R217.2
VDD_MAIN_5V: J14.10(+5V) J16.2 J16.4 R214.2
EXT40_CLK1_PC31: J16.29 ; port EXT40_CLK1_PC31
EXT40_CLK2_PB13: J16.31 ; port EXT40_CLK2_PB13
EXT40_GP5: J16.16 ; port EXT40_GP5
EXT40_GP6: J16.18 ; port EXT40_GP6
EXT40_GP7: J16.37 ; port EXT40_GP7
EXT40_GPIO_PA02: J16.11 ; port EXT40_GPIO_PA02
EXT40_GPIO_PA03: J16.15 ; port EXT40_GPIO_PA03
EXT40_GPIO_PA04: J16.13 ; port EXT40_GPIO_PA04
EXT40_GPIO_PA14: J16.22 ; port EXT40_GPIO_PA14
EXT40_GPIO_PB24: J16.36 ; port EXT40_GPIO_PB24
EXT40_I2SCK_PB19: J16.12 ; port EXT40_I2SCK_PB19
EXT40_I2SDIN_PB21: J16.38 ; port EXT40_I2SDIN_PB21
EXT40_I2SDOUT_PB22: J16.40 ; port EXT40_I2SDOUT_PB22
EXT40_I2SMCK_PB23: J16.7 ; port EXT40_I2SMCK_PB23
EXT40_I2SWS_PB20: J16.35 ; port EXT40_I2SWS_PB20
EXT40_NPCS1_PA07: J16.24 ; port EXT40_NPCS1_PA07
EXT40_NPCS2_PA08: J16.26 ; port EXT40_NPCS2_PA08
EXT40_PWM0_PB11: J16.32 ; port EXT40_PWM0_PB11
EXT40_PWM1_PB12: J16.33 ; port EXT40_PWM1_PB12
EXT40_RXD: J16.10 ; port EXT40_RXD
EXT40_SPI_MISO_PA11: J16.21 ; port EXT40_SPI_MISO_PA11
EXT40_SPI_MOSI_PA12: J16.19 ; port EXT40_SPI_MOSI_PA12
EXT40_SPI_SCLK_PA13: J16.23 ; port EXT40_SPI_SCLK_PA13
EXT40_TWCK: J16.5 ; port EXT40_TWCK
EXT40_TWD: J16.3 ; port EXT40_TWD
EXT40_TXD: J16.8 ; port EXT40_TXD
ISI_D0: J17.18 R220.1
ISI_D1: J17.19 R221.2
ISI_D2: J17.20 R222.1
ISI_D3: J17.21 R223.2
ISI_D4: J17.22 R224.1
ISI_D5: J17.23 R225.2
ISI_D6: J17.24 R226.1
ISI_D7: J17.25 R227.2
ISI_D8: J17.26 R228.1
ISI_D9: J17.27 R229.2
ISI_D10: J17.28 R230.1
ISI_D11: J17.29 R231.2
ISI_EN: J17.6 R213.1
ISI_HSYNC: J17.14 R218.1
ISI_MCK: J17.10 R215.1
ISI_nRST: J17.5 R212.2
ISI_PCK: J17.16 R219.1
ISI_VSYNC: J17.12 R216.1
LCD_D0_ISI_D0_PC00: J15.3 R220.2 ; port LCD_D0_ISI_D0_PC00
LCD_D1_ISI_D1_PC01: J15.4 R221.1 ; port LCD_D1_ISI_D1_PC01
LCD_D2_ISI_D2_PC02: J15.5 R222.2 ; port LCD_D2_ISI_D2_PC02
LCD_D3_ISI_D3_PC03: J15.6 R223.1 ; port LCD_D3_ISI_D3_PC03
LCD_D4_ISI_D4_PC04: J15.8 R224.2 ; port LCD_D4_ISI_D4_PC04
LCD_D5_ISI_D5_PC05: J15.9 R225.1 ; port LCD_D5_ISI_D5_PC05
LCD_D6_ISI_D6_PC06: J15.10 R226.2 ; port LCD_D6_ISI_D6_PC06
LCD_D7_ISI_D7_PC07: J15.11 R227.1 ; port LCD_D7_ISI_D7_PC07
LCD_D8_ISI_D8_PC08: J15.13 R228.2 ; port LCD_D8_ISI_D8_PC08
LCD_D9_ISI_D9_PC09: J15.14 R229.1 ; port LCD_D9_ISI_D9_PC09
LCD_D10_ISI_D10_PC10: J15.15 R230.2 ; port LCD_D10_ISI_D10_PC10
LCD_D11_ISI_D11_PC11: J15.16 R231.1 ; port LCD_D11_ISI_D11_PC11
LCD_D12_ISI_PCK_PC12: J15.18 R219.2 ; port LCD_D12_ISI_PCK_PC12
LCD_D13_ISI_VSYNC_PC13: J15.19 R216.2 ; port LCD_D13_ISI_VSYNC_PC13
LCD_D14_ISI_HSYNC_PC14: J15.20 R218.2 ; port LCD_D14_ISI_HSYNC_PC14
LCD_D15_ISI_MCK_PC15: J15.21 R215.2 ; port LCD_D15_ISI_MCK_PC15
LCD_D16_ISI_nRST_PC16: J15.23 R212.1 ; port LCD_D16_ISI_nRST_PC16
LCD_D17_PC17: J15.24 ; port LCD_D17_PC17
LCD_D18_PC18: J15.25 ; port LCD_D18_PC18
LCD_D19_PC19: J15.26 ; port LCD_D19_PC19
LCD_D20_PC20: J15.28 ; port LCD_D20_PC20
LCD_D21_PC21: J15.29 ; port LCD_D21_PC21
LCD_D22_PC22: J15.30 ; port LCD_D22_PC22
LCD_D23_PC23: J15.31 ; port LCD_D23_PC23
LCD_DATA_ENABLE_PC29: J15.36 ; port LCD_DATA_ENABLE_PC29
LCD_HSYNC/WE_PC28: J15.35 ; port LCD_HSYNC/WE_PC28
LCD_ID_PD14: J15.1 ; port LCD_ID_PD14
LCD_IRQ1_PC25: J15.44 ; port LCD_IRQ1_PC25
LCD_IRQ2_PB17: J15.45 ; port LCD_IRQ2_PB17
LCD_ISI_ENABLE_PC24: J15.41 R213.2 ; port LCD_ISI_ENABLE_PC24
LCD_ISI_TWCK: J15.43 J17.7 ; port LCD_ISI_TWCK
LCD_ISI_TWD: J15.42 J17.8 ; port LCD_ISI_TWD
LCD_PCLK_PC30: J15.33 ; port LCD_PCLK_PC30
LCD_PWM_PC26: J15.46 ; port LCD_PWM_PC26
LCD_VSYNC/CS_PC27: J15.34 ; port LCD_VSYNC/CS_PC27
MBUS_AD4_PB15: J14.1(AN) ; port MBUS_AD4_PB15
MBUS_INT_PB18: J14.15(INT) ; port MBUS_INT_PB18
MBUS_MISO_PA11: J14.5(MISO) ; port MBUS_MISO_PA11
MBUS_MOSI_PA12: J14.6(MOSI) ; port MBUS_MOSI_PA12
MBUS_NPCS0_PA14: J14.3(CS) ; port MBUS_NPCS0_PA14
MBUS_PWM_PB13: J14.16(PWM) ; port MBUS_PWM_PB13
MBUS_RST_PB14: J14.2(RST) ; port MBUS_RST_PB14
MBUS_RX: J14.14(RX) ; port MBUS_RX
MBUS_SPCK_PA13: J14.4(SCK) ; port MBUS_SPCK_PA13
MBUS_TWCK: J14.12(SCL) ; port MBUS_TWCK
MBUS_TWD: J14.11(SDA) ; port MBUS_TWD
MBUS_TX: J14.13(TX) ; port MBUS_TX
NRST_PB25: J15.47 ; port NRST_PB25
NetFB12_2: FB12.2 J17.1 J17.3
NetJ15_37: J15.37 R208.2
NetJ15_38: J15.38 R209.2
NetJ15_39: J15.39 R210.2
NetJ15_40: J15.40 R211.2
NetJ15_48: J15.48 J15.49 R214.1 R217.1
NetR208_1: R208.1 TP5.1
NetR209_1: R209.1 TP6.1
NetR210_1: R210.1 TP7.1
NetR211_1: R211.1 TP8.1

Not connected (* = marked no-connect by the designer): J16 27* 28*

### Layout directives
net class LCD-DATA; rule Matched Net Lengths [Tolerance = 0.5mm]: (no net found under the mark)

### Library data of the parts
?#11 = Title Block B
FB12 = IND1453: as FB10 on sheet 10 - SDMMC, CAN & CLASSD
J14 = SKT1042: Manufacturer 1: Sullins Connector Solutions; Manufacturer Part Number 1: PPTC081LFBN-RC; Description_: SOCKET mikroBUS HOST DIP 16 TH; Dev Tools Status: Production; Owner: Stephen Humberd; Populated: YES
J15 = CON1372: Manufacturer 1: Omron Electronics Inc-EMC Div; Manufacturer Part Number 1: XF2M-5015-1A; Description_: CON FFC/FPC XF2M 0.5mm 50P Female SMD R/A; Dev Tools Status: Production; Owner: Tad Ahlvers; Current: 0.5A; Populated: YES
J16 = CON0153: Manufacturer 1: Samtec; Description_: CON HDR-2.54 Male 2x20 Gold 5.84MH TH VERT; Dev Tools Status: Production; Owner: Stephen Humberd; Populated: YES
J17 = CON1580: Manufacturer 1: Wurth Electronics Inc.; Manufacturer Part Number 1: 61303021121; Description_: 30 Positions Header, Unshrouded, Breakaway Connector 0.100" (2.54mm) Through Hole Gold; Dev Tools Status: Production; Owner: Tim Moffat; Populated: YES
R208-R211 R217 = RSMT1040: Manufacturer 1: Yageo; Manufacturer Part Number 1: RC0402JR-070RL; Description_: RES TKF 0R 1/16W SMD 0402; Dev Tools Status: Production; Power: 1/16W; Owner: Sompoch Loboonlert; Populated: DNP
R212 R213 R215 R216 R218-R231 = RES1474: Manufacturer 1: Panasonic Electronic Components; Manufacturer Part Number 1: ERJ-2RKF22R0X; Description_: RES TKF 22R 1% 1/20W SMD 0402; Dev Tools Status: Production; Temperature Coeffcient: 100ppm/C; Circuit Type: Isolated; Power: 1/10W; Owner: Mike Ragsdale; Populated: YES
R214 = RSMT1040: as R135 on sheet 10 - SDMMC, CAN & CLASSD
TP5-TP8 = TEST-POINT: Test Point pad 1.00mm

## Sheet 12 - User Interaction.SchDoc
size B; CompanyName: Microchip Technology Inc.; Organization: Microchip Technology; Address1: 2355 West Chandler Blvd.; Address2: Chandler, AZ  85224; Address4: USA; DocumentNumber: 12; SheetNumber: 12; SheetTotal: 13; SheetTitle: User Interaction

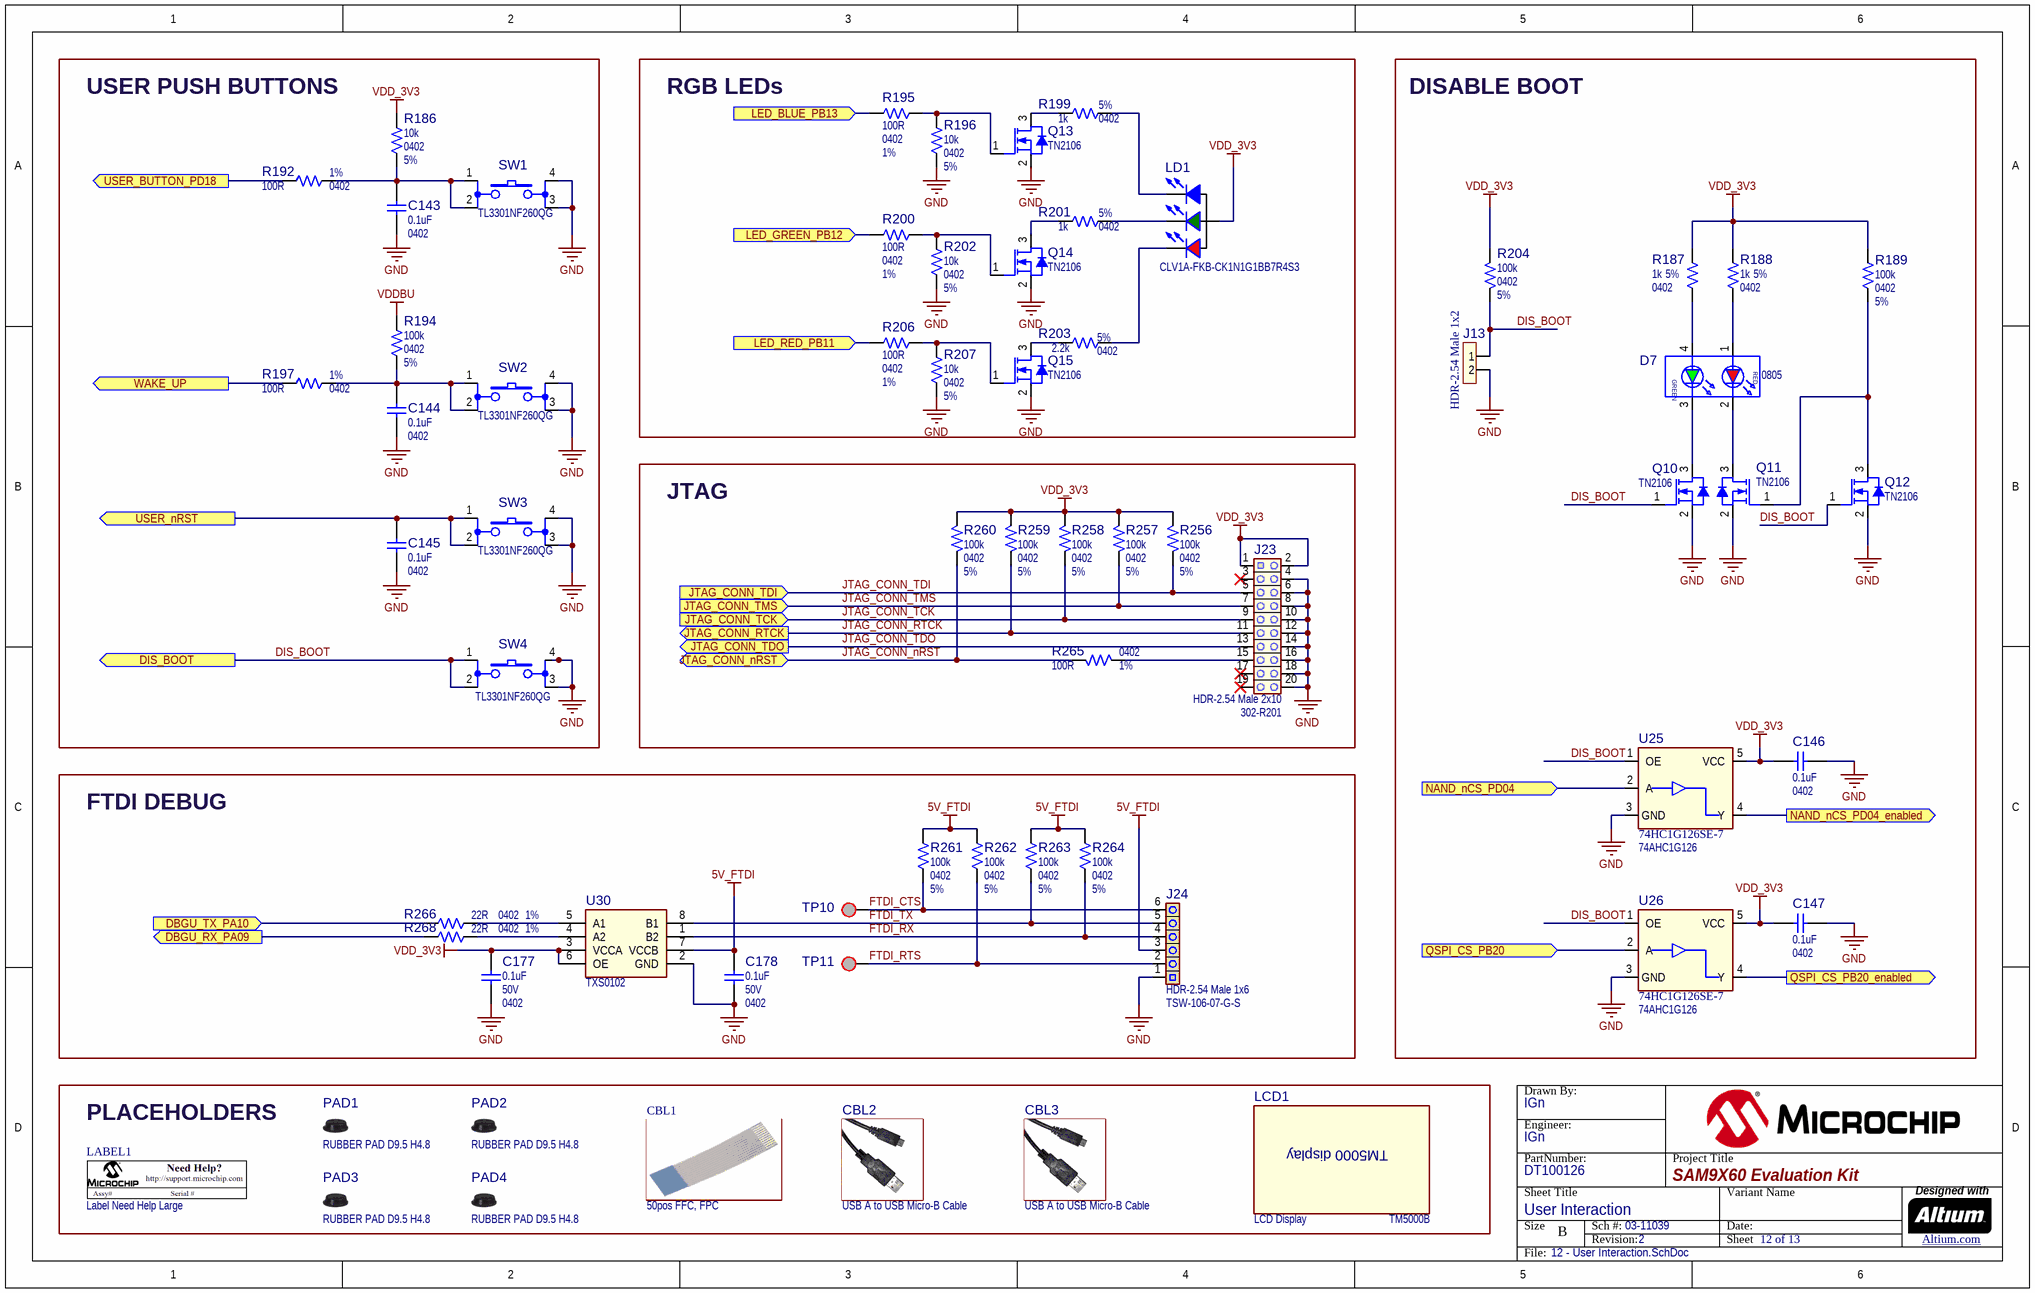
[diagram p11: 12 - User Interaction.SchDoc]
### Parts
(Parts that share a designator on the sheet are numbered #1, #2 ... from top to bottom, then left to right.)
?#12  (no value)  (graphical)
C143  value 0.1uF  Package: 0402  [CAP_C_0402]  (hidden comment: Capacitor NP)
C144  value 0.1uF  Package: 0402  [CAP_C_0402]  (hidden comment: Capacitor NP)
C145  value 0.1uF  Package: 0402  [CAP_C_0402]  (hidden comment: Capacitor NP)
C146  value 0.1uF  Package: 0402  [CAP_C_0402]  (hidden comment: Capacitor NP)
C147  value 0.1uF  Package: 0402  [CAP_C_0402]  (hidden comment: Capacitor NP)
C177  value 0.1uF  Voltage: 50V  Package: 0402  [CAP_C_0402]  (hidden comment: Capacitor NP)
C178  value 0.1uF  Voltage: 50V  Package: 0402  [CAP_C_0402]  (hidden comment: Capacitor NP)
CBL1  value 50pos FFC, FPC  (hidden comment: Cable FFC FPC Opposite Sided Contacts)  (mechanical)
CBL2  USB A to USB Micro-B Cable  (mechanical)
CBL3  USB A to USB Micro-B Cable  (mechanical)
D7  Package: 0805  [LED_DUAL_SMD_2x1.25mm]  (hidden comment: LED DUAL 4 pin)
J13  value HDR-2.54 Male 1x2  [HDR_M_2.54_1x2]  (hidden comment: Header 1x2)
J23  Voltage: HDR-2.54 Male 2x10  Manufacturer Part Number 1: 302-R201  [HDR_M_2.54_2X10_S_TH_RA_OS_302-R201]  (hidden comment: Header 2x10)
J24  value HDR-2.54 Male 1x6  Manufacturer Part Number 3: TSW-106-07-G-S  [HDR_M_2.54_1x6]  (hidden comment: Header 1x6)
LABEL1  value Label Need Help Large  [LABEL_Need_Help_Large]  (hidden comment: LABEL_Need_Help_Large)  (no BOM)
LCD1  value LCD Display  Manufacturer Part Number 1: TM5000B  [TM5000_mockup_model]  (hidden comment: TM5000 mechanical mockup)  (no BOM)
LD1  Manufacturer Part Number 1: CLV1A-FKB-CK1N1G1BB7R4S3  [PLCC-4_CLV1A-FKB]  (hidden comment: LED_RGB_CLV1A)
PAD1  value RUBBER PAD D9.5 H4.8  [BUMP_ ESSENTRA_RBS-35_CYLINDRICAL_CLEAR_D9.50H4.8]  (hidden comment: Rubber Pad Cylindrical)
PAD2  value RUBBER PAD D9.5 H4.8  [BUMP_ ESSENTRA_RBS-35_CYLINDRICAL_CLEAR_D9.50H4.8]  (hidden comment: Rubber Pad Cylindrical)
PAD3  value RUBBER PAD D9.5 H4.8  [BUMP_ ESSENTRA_RBS-35_CYLINDRICAL_CLEAR_D9.50H4.8]  (hidden comment: Rubber Pad Cylindrical)
PAD4  value RUBBER PAD D9.5 H4.8  [BUMP_ ESSENTRA_RBS-35_CYLINDRICAL_CLEAR_D9.50H4.8]  (hidden comment: Rubber Pad Cylindrical)
Q10  value TN2106  [SOT-23-3]  (hidden comment: Transistor MOS-N GSD)
Q11  value TN2106  [SOT-23-3]  (hidden comment: Transistor MOS-N GSD)
Q12  value TN2106  [SOT-23-3]  (hidden comment: Transistor MOS-N GSD)
Q13  value TN2106  [SOT-23-3]  (hidden comment: Transistor MOS-N GSD)
Q14  value TN2106  [SOT-23-3]  (hidden comment: Transistor MOS-N GSD)
Q15  value TN2106  [SOT-23-3]  (hidden comment: Transistor MOS-N GSD)
R186  value 10k  Package: 0402  Tolerance: 5%  [RES_C_0402]  (hidden comment: Resistor)
R187  value 1k  Package: 0402  Tolerance: 5%  [RES_C_0402]  (hidden comment: Resistor)
R188  value 1k  Package: 0402  Tolerance: 5%  [RES_C_0402]  (hidden comment: Resistor)
R189  value 100k  Package: 0402  Tolerance: 5%  [RES_C_0402]  (hidden comment: Resistor)
R192  value 100R  Package: 0402  Tolerance: 1%  [RES_C_0402]  (hidden comment: Resistor)
R194  value 100k  Package: 0402  Tolerance: 5%  [RES_C_0402]  (hidden comment: Resistor)
R195  value 100R  Package: 0402  Tolerance: 1%  [RES_C_0402]  (hidden comment: Resistor)
R196  value 10k  Package: 0402  Tolerance: 5%  [RES_C_0402]  (hidden comment: Resistor)
R197  value 100R  Package: 0402  Tolerance: 1%  [RES_C_0402]  (hidden comment: Resistor)
R199  value 1k  Package: 0402  Tolerance: 5%  [RES_C_0402]  (hidden comment: Resistor)
R200  value 100R  Package: 0402  Tolerance: 1%  [RES_C_0402]  (hidden comment: Resistor)
R201  value 1k  Package: 0402  Tolerance: 5%  [RES_C_0402]  (hidden comment: Resistor)
R202  value 10k  Package: 0402  Tolerance: 5%  [RES_C_0402]  (hidden comment: Resistor)
R203  value 2.2k  Package: 0402  Tolerance: 5%  [RES_C_0402]  (hidden comment: Resistor)
R204  value 100k  Package: 0402  Tolerance: 5%  [RES_C_0402]  (hidden comment: Resistor)
R206  value 100R  Package: 0402  Tolerance: 1%  [RES_C_0402]  (hidden comment: Resistor)
R207  value 10k  Package: 0402  Tolerance: 5%  [RES_C_0402]  (hidden comment: Resistor)
R256  value 100k  Package: 0402  Tolerance: 5%  [RES_C_0402]  (hidden comment: Resistor)
R257  value 100k  Package: 0402  Tolerance: 5%  [RES_C_0402]  (hidden comment: Resistor)
R258  value 100k  Package: 0402  Tolerance: 5%  [RES_C_0402]  (hidden comment: Resistor)
R259  value 100k  Package: 0402  Tolerance: 5%  [RES_C_0402]  (hidden comment: Resistor)
R260  value 100k  Package: 0402  Tolerance: 5%  [RES_C_0402]  (hidden comment: Resistor)
R261  value 100k  Package: 0402  Tolerance: 5%  [RES_C_0402]  (hidden comment: Resistor)
R262  value 100k  Package: 0402  Tolerance: 5%  [RES_C_0402]  (hidden comment: Resistor)
R263  value 100k  Package: 0402  Tolerance: 5%  [RES_C_0402]  (hidden comment: Resistor)
R264  value 100k  Package: 0402  Tolerance: 5%  [RES_C_0402]  (hidden comment: Resistor)
R265  value 100R  Package: 0402  Tolerance: 1%  [RES_C_0402]  (hidden comment: Resistor)
R266  value 22R  Package: 0402  Tolerance: 1%  [RES_C_0402]  (hidden comment: Resistor)
R268  value 22R  Package: 0402  Tolerance: 1%  [RES_C_0402]  (hidden comment: Resistor)
SW1  Manufacturer Part Number 2: TL3301NF260QG  [SW_SMD_6mmX6mm_TL3301]  (hidden comment: Switch 4 Pin)
SW2  Manufacturer Part Number 2: TL3301NF260QG  [SW_SMD_6mmX6mm_TL3301]  (hidden comment: Switch 4 Pin)
SW3  Manufacturer Part Number 2: TL3301NF260QG  [SW_SMD_6mmX6mm_TL3301]  (hidden comment: Switch 4 Pin)
SW4  Manufacturer Part Number 2: TL3301NF260QG  [SW_SMD_6mmX6mm_TL3301]  (hidden comment: Switch 4 Pin)
TP10  SMD Test Point  [TP_1x1_SMD]  (value not drawn)  (no BOM)
TP11  SMD Test Point  [TP_1x1_SMD]  (value not drawn)  (no BOM)
U25  74HC1G126SE-7  value 74AHC1G126  [SC-70-5]
U26  74HC1G126SE-7  value 74AHC1G126  [SC-70-5]
U30  TXS0102  [US-8]

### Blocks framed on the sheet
USER PUSH BUTTONS: C143-C145 R186 R192 R194 R197 SW1-SW4
RGB LEDs: LD1 Q13-Q15 R195 R196 R199-R203 R206 R207
DISABLE BOOT: C146 C147 D7 J13 Q10-Q12 R187-R189 R204 U25 U26
JTAG: J23 R256-R260 R265
FTDI DEBUG: C177 C178 J24 R261-R264 R266 R268 TP10 TP11 U30
PLACEHOLDERS: CBL1-CBL3 LABEL1 LCD1 PAD1-PAD4

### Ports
DBGU_RX_PA09 (out), DBGU_TX_PA10 (in), DIS_BOOT (out), JTAG_CONN_nRST (bidir), JTAG_CONN_RTCK (out), JTAG_CONN_TCK (in), JTAG_CONN_TDI (in), JTAG_CONN_TDO (out), JTAG_CONN_TMS (in), LED_BLUE_PB13 (in), LED_GREEN_PB12 (in), LED_RED_PB11 (in), NAND_nCS_PD04 (in), NAND_nCS_PD04_enabled (out), QSPI_CS_PB20 (in), QSPI_CS_PB20_enabled (out), USER_BUTTON_PD18 (out), USER_nRST (out), WAKE_UP (out)

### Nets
5V_FTDI: C178.2 J24.3 R261.1 R262.1 R263.2 R264.2 U30.7(VCCB)
GND: C143.2 C144.2 C145.2 C146.1 C147.1 C177.1 C178.1 J13.2 J23.4 J23.6 J23.8 J23.10 J23.12 J23.14 J23.16 J23.18 J23.20 J24.1 Q10.2(S) Q11.2(S) Q12.2(S) Q13.2(S) Q14.2(S) Q15.2(S) R196.2 R202.2 R207.2 SW1.3 SW1.4 SW2.3 SW2.4 SW3.3 SW3.4 SW4.3 SW4.4 U25.3(GND) U26.3(GND) U30.2(GND)
VDD_3V3: C146.2 C147.2 C177.2 J23.1 J23.2 LD1.2(A) R186.1 R187.1 R188.1 R189.2 R204.2 R256.2 R257.2 R258.1 R259.1 R260.2 U25.5(VCC) U26.5(VCC) U30.3(VCCA) U30.6(OE)
VDDBU: R194.2
DBGU_RX_PA09: R268.1 ; port DBGU_RX_PA09
DBGU_TX_PA10: R266.1 ; port DBGU_TX_PA10
DIS_BOOT: J13.1 Q10.1(G) Q12.1(G) R204.1 SW4.1 SW4.2 U25.1(OE) U26.1(OE) ; port DIS_BOOT
FTDI_CTS: J24.6 R261.2 TP10.1
FTDI_RTS: J24.2 R262.2 TP11.1
FTDI_RX: J24.4 R264.1 U30.1(B2)
FTDI_TX: J24.5 R263.1 U30.8(B1)
JTAG_CONN_nRST: R260.1 R265.1 ; port JTAG_CONN_nRST
JTAG_CONN_RTCK: J23.11 R259.2 ; port JTAG_CONN_RTCK
JTAG_CONN_TCK: J23.9 R258.2 ; port JTAG_CONN_TCK
JTAG_CONN_TDI: J23.5 R256.1 ; port JTAG_CONN_TDI
JTAG_CONN_TDO: J23.13 ; port JTAG_CONN_TDO
JTAG_CONN_TMS: J23.7 R257.1 ; port JTAG_CONN_TMS
NAND_nCS_PD04: U25.2(A) ; port NAND_nCS_PD04
NAND_nCS_PD04_enabled: U25.4(Y) ; port NAND_nCS_PD04_enabled
PB11: R206.1 ; port LED_RED_PB11
PB12: R200.1 ; port LED_GREEN_PB12
PB13: R195.1 ; port LED_BLUE_PB13
QSPI_CS_PB20: U26.2(A) ; port QSPI_CS_PB20
QSPI_CS_PB20_enabled: U26.4(Y) ; port QSPI_CS_PB20_enabled
USER_BUTTON_PD18: R192.1 ; port USER_BUTTON_PD18
USER_nRST: C145.1 SW3.1 SW3.2 ; port USER_nRST
WAKE_UP: R197.1 ; port WAKE_UP
NetC143_1: C143.1 R186.2 R192.2 SW1.1 SW1.2
NetC144_1: C144.1 R194.1 R197.2 SW2.1 SW2.2
NetD7_1: D7.1(A1) R188.2
NetD7_2: D7.2(K1) Q11.3(D)
NetD7_3: D7.3(K2) Q10.3(D)
NetD7_4: D7.4(A2) R187.2
NetJ23_15: J23.15 R265.2
NetLD1_1: LD1.1(Kr) R203.2
NetLD1_3: LD1.3(Kb) R199.2
NetLD1_4: LD1.4(Kg) R201.2
NetQ11_1: Q11.1(G) Q12.3(D) R189.1
NetQ13_1: Q13.1(G) R195.2 R196.1
NetQ13_3: Q13.3(D) R199.1
NetQ14_1: Q14.1(G) R200.2 R202.1
NetQ14_3: Q14.3(D) R201.1
NetQ15_1: Q15.1(G) R206.2 R207.1
NetQ15_3: Q15.3(D) R203.1
NetR266_2: R266.2 U30.5(A1)
NetR268_2: R268.2 U30.4(A2)

Not connected (* = marked no-connect by the designer): J23 3* 17* 19*

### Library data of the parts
?#12 = Title Block B
C143-C147 = CAP1463: Capacitor; Manufacturer 1: TDK Corporation; Manufacturer Part Number 1: C1005X7R1H104K050BB; Voltage: 50V; Description_: CAP CER 0.1uF 50V 10% X7R SMD 0402; Dev Tools Status: Production; Tolerance: 10%; Temperature Coeffcient: X7R; Type: Ceramic; Owner: Jamus Griego; Populated: YES
C177 C178 = CAP1463: as C95 on sheet 10 - SDMMC, CAN & CLASSD
CBL1 = CAB1019: Manufacturer 1: Wurth Electronics Inc.; Manufacturer Part Number 1: 687750100002; Description_: MECH HW CABLE FFC, FPC 50pos 0.50mm 100mm; Dev Tools Status: Design; Owner: Ilie Galan; Populated: MECH
CBL2 CBL3 = CAB1020: Manufacturer 1: Assmann WSW Components; Manufacturer Part Number 1: AK67421-1; Description_: MECH HW CABLE USB Male A TO USB Male Micro-B 1M; Dev Tools Status: Design; Owner: Ilie Galan; Populated: MECH
D7 = DIODE1110: LED; Manufacturer 1: Kingbright Corp; Manufacturer Part Number 1: APHBM2012SURKCGKC; Value: RED, GREEN; Description_: DIO LED BI RED, GREEN 1.95V, 2.1V 30mA 0805; Dev Tools Status: Production; Type: LED Bicolor; Forward Current: 30mA; Power: 75mW; Reverse Current: 10uA; Owner: Bogdan P (M91398); Populated: Yes
J13 = CON1312: Manufacturer 1: Sullins Connector Solutions; Manufacturer Part Number 1: PREC002SAAN-RC; Description_: CON HDR-2.54 Male 1x2 Tin 5.84MH TH VERT; Dev Tools Status: Production; Owner: Randolph Sobrepena; Populated: YES
J23 = CON1883: Manufacturer 1: On Shore Technology Inc.; Description_: CONN HDR-2.54 MALE 2x10 GOLD SHROUD 3.10MH TH R/A; Dev Tools Status: Design; Owner: Ilie Galan; Current: 3A; Populated: YES
J24 = CON1106: Manufacturer 1: FCI; Manufacturer Part Number 1: 68000-106HLF; Description_: CON HDR-2.54 Male 1x6 Gold 5.84MH TH VERT; Dev Tools Status: Production; Owner: Bogdan P (M91398); Populated: Yes
LABEL1 = 08-00126: Description_: LABEL, NEED HELP WITH ASSY/SERIAL; Dev Tools Status: Production; Populated: MECH
LCD1 = DISPLAY0025: Manufacturer 1: PDA INC; Description_: DISPLAY LCD TM5000B 5" GRAPHICAL 5V SCREWS; Dev Tools Status: Design; Owner: Dragos Danaila; Voltage: 5V; Populated: YES
LD1 = DIODE1214: Manufacturer 1: Cree Inc; Value: RED, GREEN, BLUE; Description_: DIO LED TRI RED, GREEN, BLUE 2V, 3.2V, 3.2V 20mA, 20mA, 20mA SMD 4-PLCC; Dev Tools Status: Production; Type: LED Tricolor; Forward Current: 20mA, 20mA, 20mA; Power: 130mW, 100mW, 100mW; Reverse Current: 10uA; Reverse Voltage: 5V; Owner: Randolph Sobrepena; Populated: YES
PAD1-PAD4 = MECH0185: Manufacturer 1: Essentra Components; Manufacturer Part Number 1: RBS-35; Description_: MECH HW RUBBER PAD Cylindrical, 0.374" x 0.189" Clear; Dev Tools Status: Design; Owner: Sam Charles; Populated: MECH
Q10-Q15 = MIC7420: Transistor MOS; Manufacturer 1: Microchip Technology; Manufacturer Part Number 1: TN2106K1-G; Description_: MCHP ANALOG MOSFET N-CH TN2106 60V 280mA 360mW 2.5R SOT23-3; Type: MOSFET; Dev Tools Status: Production; Owner: Ilie Galan; Populated: YES
R186 R196 R202 = RSMT0439: as R108-R113 on sheet 10 - SDMMC, CAN & CLASSD
R187 R188 R199 R201 = RSMT0316: Manufacturer 1: Panasonic; Manufacturer Part Number 1: ERJ-2GEJ102X; Description_: RES TKF 1k 5% 1/16W SMD 0402; Dev Tools Status: Production; Voltage: 50V; Temperature Coeffcient: 200ppm/C; Power: 1/16W; Owner: Tad Ahlvers; Populated: YES
R189 R194 R204 R256 R257 R260 R263 R264 = RES2196: Manufacturer 1: Yageo; Manufacturer Part Number 1: RC0402JR-07100KL; Description_: RES TKF 100k 5% 1/16W SMD 0402; Dev Tools Status: Design; Temperature Coeffcient: 100ppm/C; Power: 1/16W; Owner: Ilie Galan; Populated: YES
R192 R195 R197 R200 R206 R265 = RES1587: Manufacturer 1: Yageo; Manufacturer Part Number 1: RC0402FR-07100RL; Description_: RES TKF 100R 1% 1/16W SMD 0402; Dev Tools Status: Design; Voltage: 50V; Temperature Coeffcient: 100ppm/C; Power: 1/16W; Owner: Sorin Stanoaia; Populated: YES
R203 = RES1020: Manufacturer 1: Vishay Dale; Manufacturer Part Number 1: CRCW04022K20JNED; Description_: RES TKF 2.2k 5% 1/16W SMD 0402; Dev Tools Status: Production; Voltage: 50V; Temperature Coeffcient: 200ppm/C; Power: 1/16W; Owner: Tad Ahlvers; Populated: YES
R207 = RSMT0439: as R118 on sheet 10 - SDMMC, CAN & CLASSD
R258 R259 R261 R262 = RES2196: Manufacturer 1: Yageo; Manufacturer Part Number 1: RC0402JR-07100KL; Description_: RES TKF 100k 5% 1/16W SMD 0402; Dev Tools Status: Design; Temperature Coeffcient: 100ppm/C; Power: 1/16W; Owner: Ilie Galan; Populated: DNP
R266 R268 = RES1474: as R212 on sheet 11 - Expansion connectors
SW1-SW4 = SWITCH0003: Switch; Manufacturer 1: E-Switch; Manufacturer Part Number 1: TL3301NF260QG/TR; Value: TACT SPST; Description_: SWITCH TACT SPST 12V 50mA TL3301NF160QG/TR SMD; Dev Tools Status: Production; Voltage: 12V; Current: 50mA; Populated: Yes
TP10 TP11 = TEST-POINT: Test Point pad 1.00mm
U25 U26 = IC1252: Single  Non-Inverting 3-State  buffer; Manufacturer 1: Diodes Incorporated; Manufacturer Part Number 1: 74AHC1G126SE-7; MCHP-ID: IC1252; Description_: IC BUFFER 74AHC1G126SE-7 SINGLE SC-70-5; Dev Tools Status: Design; Owner: Ed Kennedy; Populated: YES
U30 = IC1128: Level Shifter; Manufacturer 1: Texas Instruments; Manufacturer Part Number 1: TXS0102DCUR; MCHP-ID: IC1128; Description_: IC TRANSCEIVER TXS0102 US-8; Dev Tools Status: Production; Owner: Bogdan P (M91398); Populated: Yes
